FUNCTION "Gest Automatico Linea" : VOID
TITLE =Gestione Ciclo Automatico
AUTHOR : MassimoZ
FAMILY : NovaSrl
VERSION : 0.1

BEGIN
NETWORK
TITLE ======== Ciclo Automatico Zona Acc. 1 =======

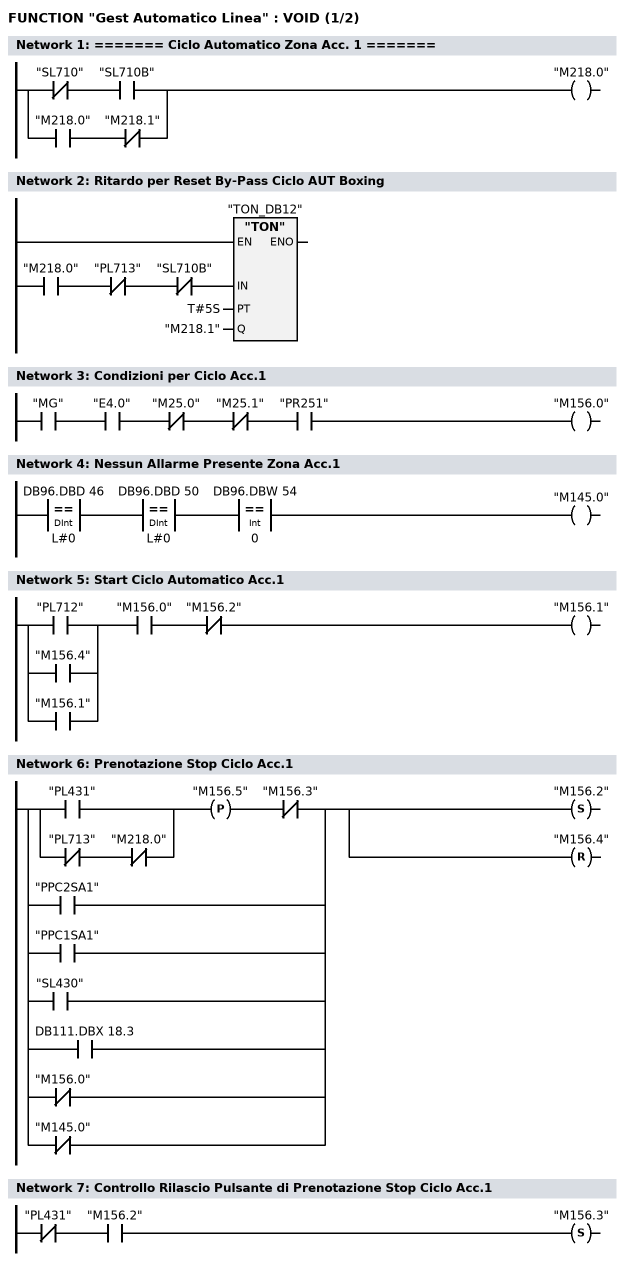
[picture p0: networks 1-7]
      UN    "SL710";
      U     "SL710B";
      O     ;
      U     "M218.0";
      UN    "M218.1";
      =     "M218.0";
NETWORK
TITLE =Ritardo per Reset By-Pass Ciclo AUT Boxing

      U     "M218.0";
      UN    "PL713";
      UN    "SL710B";
      =     L      0.0;
      BLD   103;
      CALL "TON" , "TON_DB12" (
           IN                       := L      0.0,
           PT                       := T#5S,
           Q                        := "M218.1");

      NOP   0;
NETWORK
TITLE =Condizioni per Ciclo Acc.1

      U     "MG";
      U     "E4.0";
      UN    "M25.0";
      UN    "M25.1";
      U     "PR251";
      =     "M156.0";
NETWORK
TITLE =Nessun Allarme Presente Zona Acc.1

      U(    ;
      L     DB96.DBD   46;
      L     L#0;
      ==D   ;
      )     ;
      U(    ;
      L     DB96.DBD   50;
      L     L#0;
      ==D   ;
      )     ;
      U(    ;
      L     DB96.DBW   54;
      L     0;
      ==I   ;
      )     ;
      =     "M145.0";
NETWORK
TITLE =Start Ciclo Automatico Acc.1

      U(    ;
      O     "PL712";
      O     "M156.4";
      O     "M156.1";
      )     ;
      U     "M156.0";
      UN    "M156.2";
      =     "M156.1";
NETWORK
TITLE =Prenotazione Stop Ciclo Acc.1

      U(    ;
      O     "PL431";
      O     ;
      UN    "PL713";
      UN    "M218.0";
      )     ;
      FP    "M156.5";
      UN    "M156.3";
      O     "PPC2SA1";
      O     "PPC1SA1";
      O     "SL430";
      O     DB111.DBX   18.3;
      ON    "M156.0";
      ON    "M145.0";
      S     "M156.2";
      R     "M156.4";
NETWORK
TITLE =Controllo Rilascio Pulsante di Prenotazione Stop Ciclo Acc.1

      UN    "PL431";
      U     "M156.2";
      S     "M156.3";
NETWORK
TITLE =Riavviamento Ciclo dopo Prenotazione Stop Ciclo Acc.1

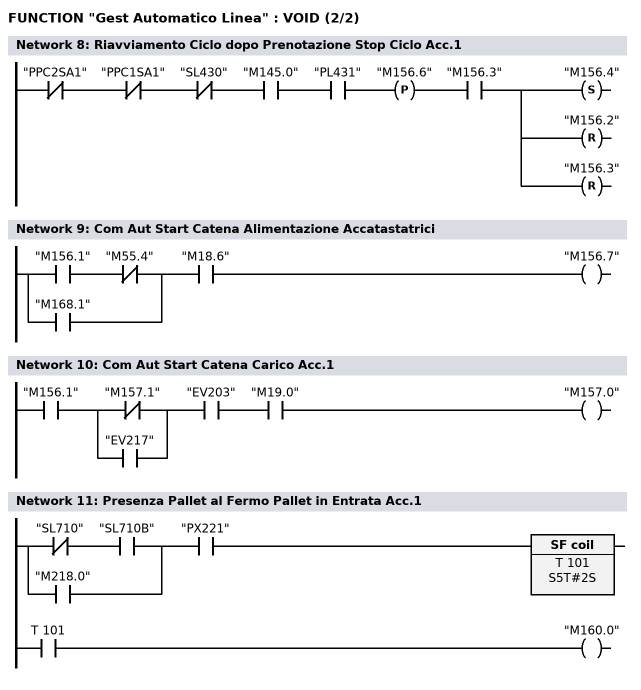
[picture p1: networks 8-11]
      UN    "PPC2SA1";
      UN    "PPC1SA1";
      UN    "SL430";
      U     "M145.0";
      U     "PL431";
      FP    "M156.6";
      U     "M156.3";
      S     "M156.4";
      R     "M156.2";
      R     "M156.3";
NETWORK
TITLE =Com Aut Start Catena Alimentazione Accatastatrici

      U(    ;
      U     "M156.1";
      UN    "M55.4";
      O     "M168.1";
      )     ;
      U     "M18.6";
      =     "M156.7";
NETWORK
TITLE =Com Aut Start Catena Carico Acc.1

      U     "M156.1";
      U(    ;
      ON    "M157.1";
      O     "EV217";
      )     ;
      U     "EV203";
      U     "M19.0";
      =     "M157.0";
NETWORK
TITLE =Presenza Pallet al Fermo Pallet in Entrata Acc.1

      U(    ;
      UN    "SL710";
      U     "SL710B";
      O     "M218.0";
      )     ;
      U     "PX221";
      L     S5T#2S;
      SA    T    101;
      NOP   0;
      NOP   0;
      NOP   0;
      U     T    101;
      =     "M160.0";
NETWORK
TITLE =Presenza Pallet in Posizione di Arrivo Acc.1

      U(    ;
      U(    ;
      UN    "SL710";
      U     "SL710B";
      O     "M218.0";
      )     ;
      U     "PX222";
      L     S5T#2S;
      SE    T     16;
      NOP   0;
      NOP   0;
      NOP   0;
      U     T     16;
      )     ;
      L     S5T#4S;
      SA    T     23;
      NOP   0;
      NOP   0;
      NOP   0;
      U     T     23;
      =     "M157.1";
NETWORK
TITLE =Presenza Pallet in Posizione Carico 1 Acc.1

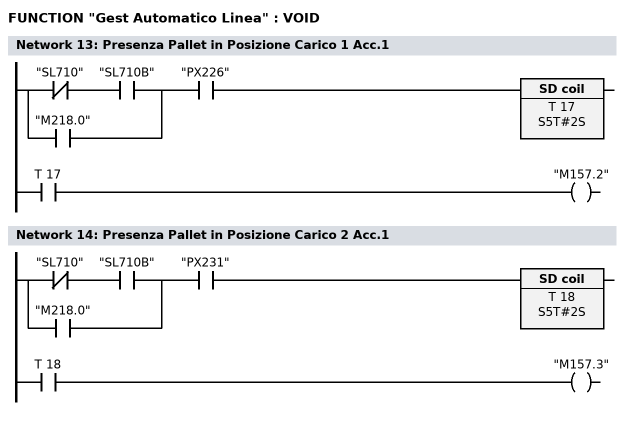
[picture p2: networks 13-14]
      U(    ;
      UN    "SL710";
      U     "SL710B";
      O     "M218.0";
      )     ;
      U     "PX226";
      L     S5T#2S;
      SE    T     17;
      NOP   0;
      NOP   0;
      NOP   0;
      U     T     17;
      =     "M157.2";
NETWORK
TITLE =Presenza Pallet in Posizione Carico 2 Acc.1

      U(    ;
      UN    "SL710";
      U     "SL710B";
      O     "M218.0";
      )     ;
      U     "PX231";
      L     S5T#2S;
      SE    T     18;
      NOP   0;
      NOP   0;
      NOP   0;
      U     T     18;
      =     "M157.3";
NETWORK
TITLE =Presenza Pallet in Posizione Scarico 2 Acc.1

      U(    ;
      U(    ;
      UN    "SL710";
      U     "SL710B";
      O     "M218.0";
      )     ;
      U     "PX233";
      L     S5T#500MS;
      SE    T     21;
      NOP   0;
      NOP   0;
      NOP   0;
      U     T     21;
      )     ;
      L     S5T#2S;
      SA    T     22;
      NOP   0;
      NOP   0;
      NOP   0;
      U     T     22;
      =     "M157.4";
NETWORK
TITLE =Com Aut Salita Fermo Pallet in Uscita per alimentazione Acc.2

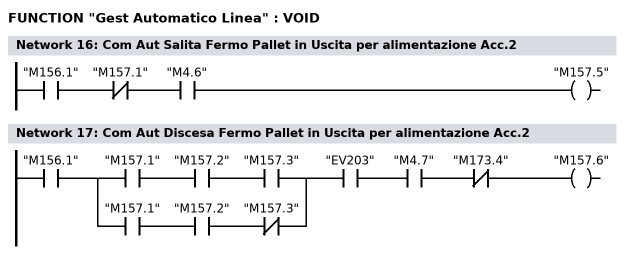
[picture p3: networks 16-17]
      U     "M156.1";
      UN    "M157.1";
      U     "M4.6";
      =     "M157.5";
NETWORK
TITLE =Com Aut Discesa Fermo Pallet in Uscita per alimentazione Acc.2

      U     "M156.1";
      U(    ;
      U     "M157.1";
      U     "M157.2";
      U     "M157.3";
      O     ;
      U     "M157.1";
      U     "M157.2";
      UN    "M157.3";
      )     ;
      U     "EV203";
      U     "M4.7";
      UN    "M173.4";
      =     "M157.6";
NETWORK
TITLE =Aut Pallet in traslazione verso Acc.2

      U     "M157.6";
      S     "M173.4";
      U(    ;
      U     "PX191";
      L     S5T#1S500MS;
      SA    T    104;
      NOP   0;
      NOP   0;
      NOP   0;
      U     T    104;
      )     ;
      FN    "M173.5";
      R     "M173.4";
      NOP   0;
NETWORK
TITLE =Com Aut Avanti Fermo Pallet in Arrivo Acc.1

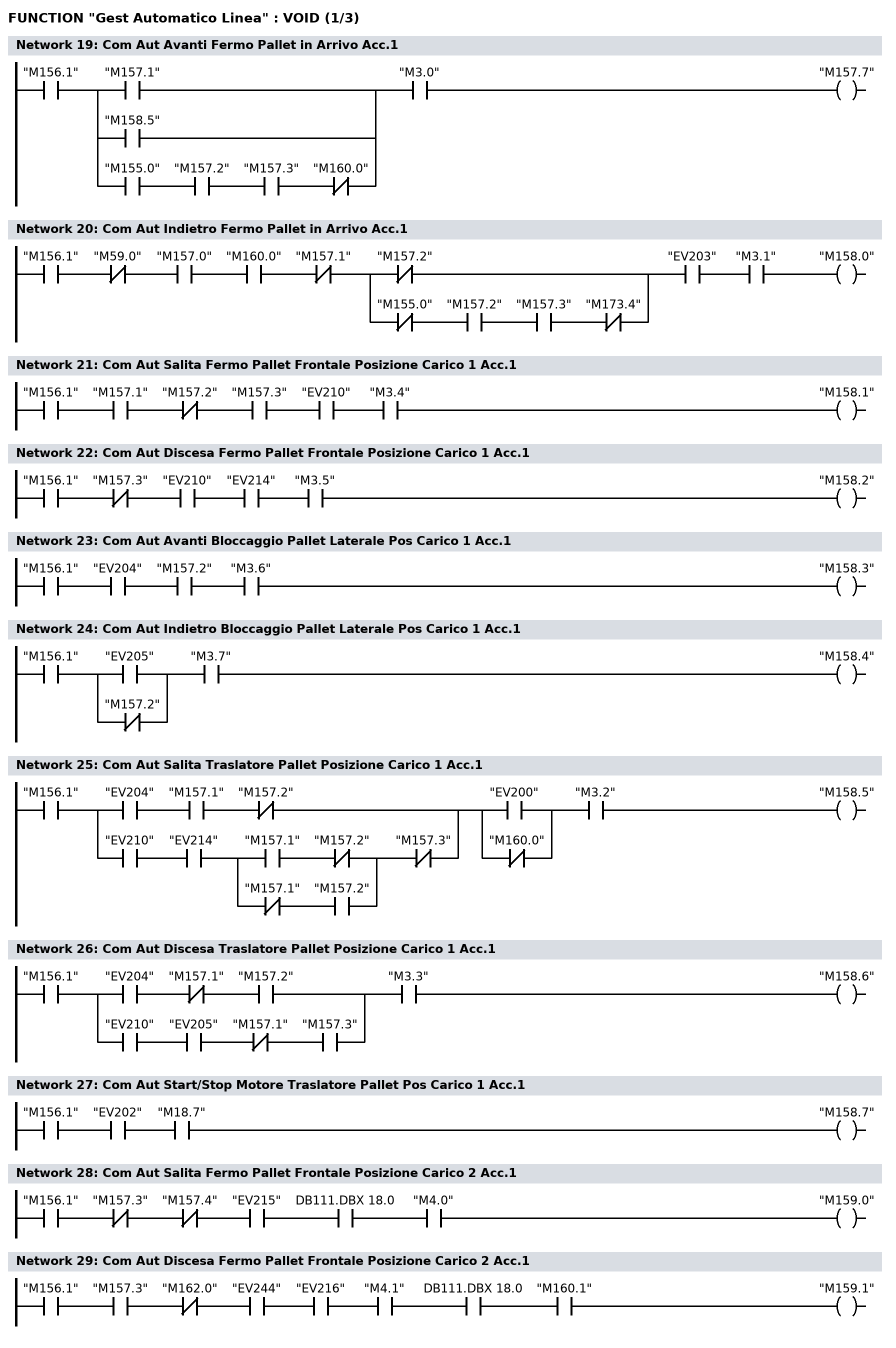
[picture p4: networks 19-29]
      U     "M156.1";
      U(    ;
      O     "M157.1";
      O     "M158.5";
      O     ;
      U     "M155.0";
      U     "M157.2";
      U     "M157.3";
      UN    "M160.0";
      )     ;
      U     "M3.0";
      =     "M157.7";
NETWORK
TITLE =Com Aut Indietro Fermo Pallet in Arrivo Acc.1

      U     "M156.1";
      UN    "M59.0";
      U     "M157.0";
      U     "M160.0";
      UN    "M157.1";
      U(    ;
      ON    "M157.2";
      O     ;
      UN    "M155.0";
      U     "M157.2";
      U     "M157.3";
      UN    "M173.4";
      )     ;
      U     "EV203";
      U     "M3.1";
      =     "M158.0";
NETWORK
TITLE =Com Aut Salita Fermo Pallet Frontale Posizione Carico 1 Acc.1

      U     "M156.1";
      U     "M157.1";
      UN    "M157.2";
      U     "M157.3";
      U     "EV210";
      U     "M3.4";
      =     "M158.1";
NETWORK
TITLE =Com Aut Discesa Fermo Pallet Frontale Posizione Carico 1 Acc.1

      U     "M156.1";
      UN    "M157.3";
      U     "EV210";
      U     "EV214";
      U     "M3.5";
      =     "M158.2";
NETWORK
TITLE =Com Aut Avanti Bloccaggio Pallet Laterale Pos Carico 1 Acc.1

      U     "M156.1";
      U     "EV204";
      U     "M157.2";
      U     "M3.6";
      =     "M158.3";
NETWORK
TITLE =Com Aut Indietro Bloccaggio Pallet Laterale Pos Carico 1 Acc.1

      U     "M156.1";
      U(    ;
      O     "EV205";
      ON    "M157.2";
      )     ;
      U     "M3.7";
      =     "M158.4";
NETWORK
TITLE =Com Aut Salita Traslatore Pallet Posizione Carico 1 Acc.1

      U     "M156.1";
      U(    ;
      U     "EV204";
      U     "M157.1";
      UN    "M157.2";
      O     ;
      U     "EV210";
      U     "EV214";
      U(    ;
      U     "M157.1";
      UN    "M157.2";
      O     ;
      UN    "M157.1";
      U     "M157.2";
      )     ;
      UN    "M157.3";
      )     ;
      U(    ;
      O     "EV200";
      ON    "M160.0";
      )     ;
      U     "M3.2";
      =     "M158.5";
NETWORK
TITLE =Com Aut Discesa Traslatore Pallet Posizione Carico 1 Acc.1

      U     "M156.1";
      U(    ;
      U     "EV204";
      UN    "M157.1";
      U     "M157.2";
      O     ;
      U     "EV210";
      U     "EV205";
      UN    "M157.1";
      U     "M157.3";
      )     ;
      U     "M3.3";
      =     "M158.6";
NETWORK
TITLE =Com Aut Start/Stop Motore Traslatore Pallet Pos Carico 1 Acc.1

      U     "M156.1";
      U     "EV202";
      U     "M18.7";
      =     "M158.7";
NETWORK
TITLE =Com Aut Salita Fermo Pallet Frontale Posizione Carico 2 Acc.1

      U     "M156.1";
      UN    "M157.3";
      UN    "M157.4";
      U     "EV215";
      U     DB111.DBX   18.0;
      U     "M4.0";
      =     "M159.0";
NETWORK
TITLE =Com Aut Discesa Fermo Pallet Frontale Posizione Carico 2 Acc.1

      U     "M156.1";
      U     "M157.3";
      UN    "M162.0";
      U     "EV244";
      U     "EV216";
      U     "M4.1";
      U     DB111.DBX   18.0;
      U     "M160.1";
      =     "M159.1";
NETWORK
TITLE =Com Aut Avanti Bloccaggio Pallet Laterale Pos Carico 2 Acc.1

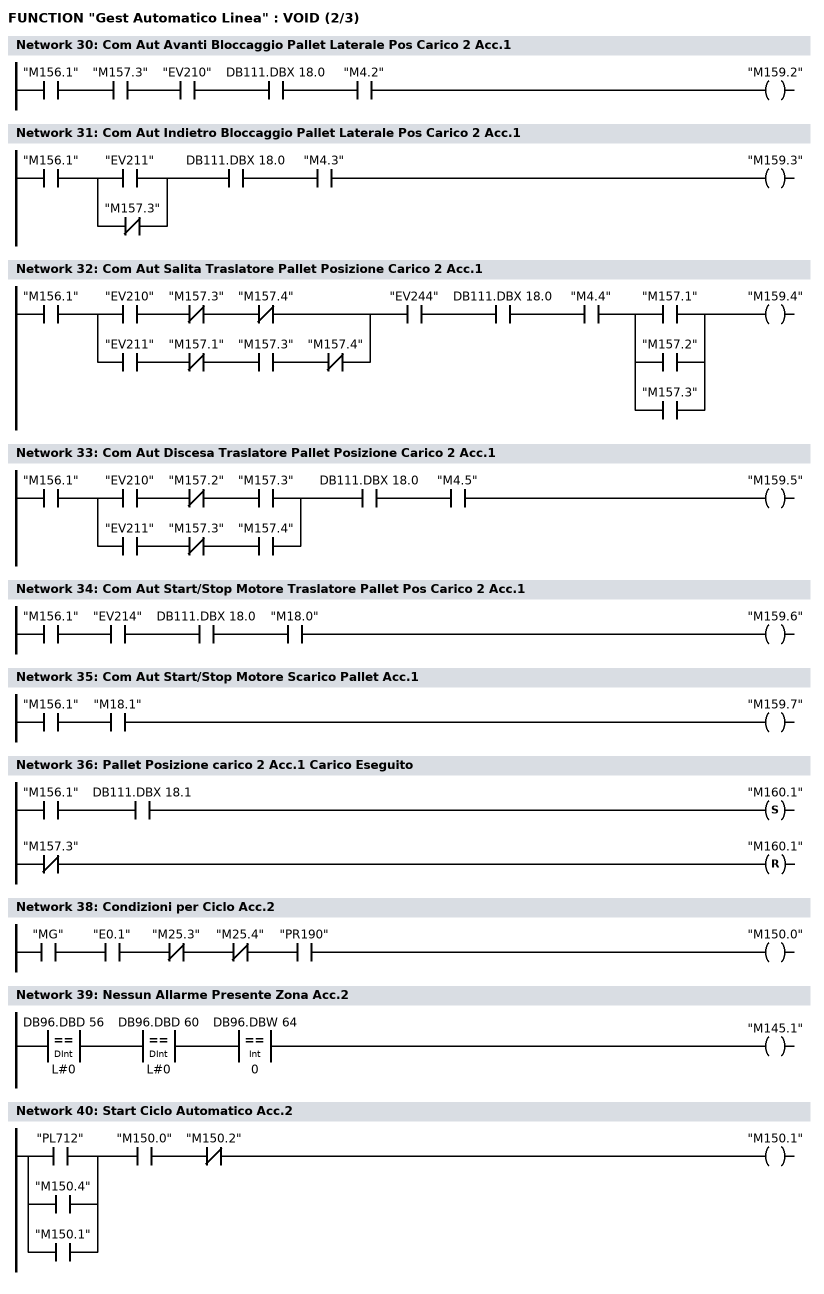
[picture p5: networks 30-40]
      U     "M156.1";
      U     "M157.3";
      U     "EV210";
      U     DB111.DBX   18.0;
      U     "M4.2";
      =     "M159.2";
NETWORK
TITLE =Com Aut Indietro Bloccaggio Pallet Laterale Pos Carico 2 Acc.1

      U     "M156.1";
      U(    ;
      O     "EV211";
      ON    "M157.3";
      )     ;
      U     DB111.DBX   18.0;
      U     "M4.3";
      =     "M159.3";
NETWORK
TITLE =Com Aut Salita Traslatore Pallet Posizione Carico 2 Acc.1

      U     "M156.1";
      U(    ;
      U     "EV210";
      UN    "M157.3";
      UN    "M157.4";
      O     ;
      U     "EV211";
      UN    "M157.1";
      U     "M157.3";
      UN    "M157.4";
      )     ;
      U     "EV244";
      U     DB111.DBX   18.0;
      U     "M4.4";
      U(    ;
      O     "M157.1";
      O     "M157.2";
      O     "M157.3";
      )     ;
      =     "M159.4";
NETWORK
TITLE =Com Aut Discesa Traslatore Pallet Posizione Carico 2 Acc.1

      U     "M156.1";
      U(    ;
      U     "EV210";
      UN    "M157.2";
      U     "M157.3";
      O     ;
      U     "EV211";
      UN    "M157.3";
      U     "M157.4";
      )     ;
      U     DB111.DBX   18.0;
      U     "M4.5";
      =     "M159.5";
NETWORK
TITLE =Com Aut Start/Stop Motore Traslatore Pallet Pos Carico 2 Acc.1

      U     "M156.1";
      U     "EV214";
      U     DB111.DBX   18.0;
      U     "M18.0";
      =     "M159.6";
NETWORK
TITLE =Com Aut Start/Stop Motore Scarico Pallet Acc.1

      U     "M156.1";
      U     "M18.1";
      =     "M159.7";
NETWORK
TITLE =Pallet Posizione carico 2 Acc.1 Carico Eseguito

      U     "M156.1";
      U     DB111.DBX   18.1;
      S     "M160.1";
      UN    "M157.3";
      R     "M160.1";
      NOP   0;
NETWORK
TITLE ======== Ciclo Automatico Zona Acc. 2 =======



NETWORK
TITLE =Condizioni per Ciclo Acc.2

      U     "MG";
      U     "E0.1";
      UN    "M25.3";
      UN    "M25.4";
      U     "PR190";
      =     "M150.0";
NETWORK
TITLE =Nessun Allarme Presente Zona Acc.2

      U(    ;
      L     DB96.DBD   56;
      L     L#0;
      ==D   ;
      )     ;
      U(    ;
      L     DB96.DBD   60;
      L     L#0;
      ==D   ;
      )     ;
      U(    ;
      L     DB96.DBW   64;
      L     0;
      ==I   ;
      )     ;
      =     "M145.1";
NETWORK
TITLE =Start Ciclo Automatico Acc.2

      U(    ;
      O     "PL712";
      O     "M150.4";
      O     "M150.1";
      )     ;
      U     "M150.0";
      UN    "M150.2";
      =     "M150.1";
NETWORK
TITLE =Prenotazione Stop Ciclo Acc.2

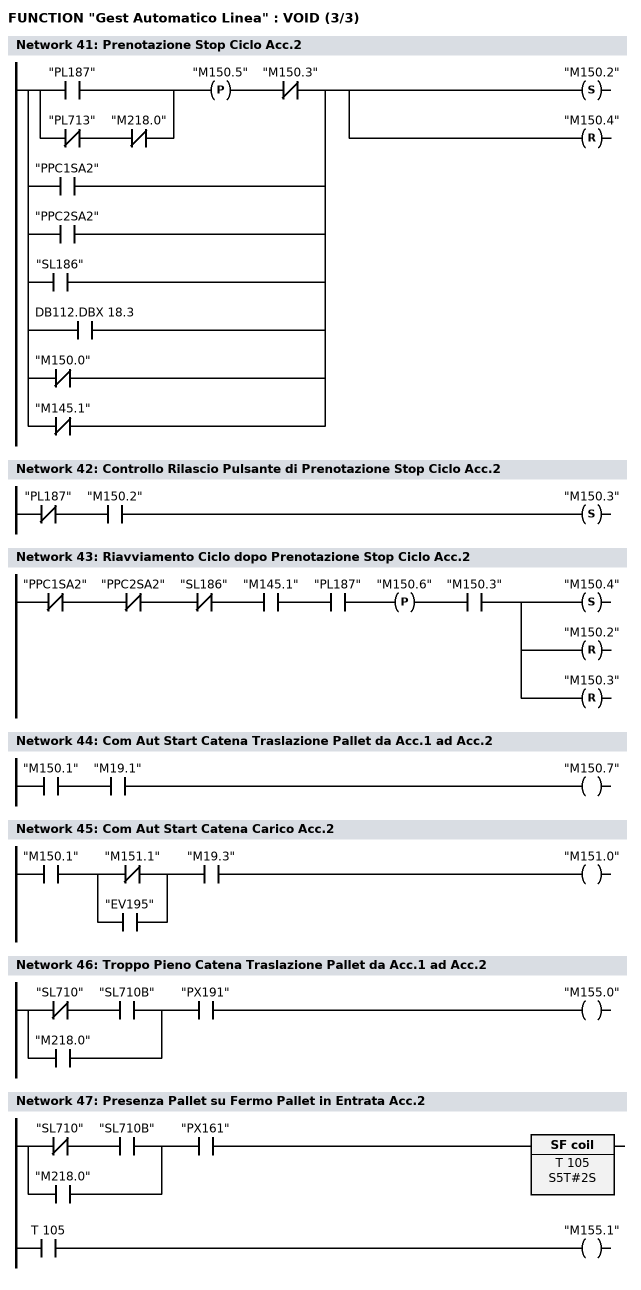
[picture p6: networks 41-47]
      U(    ;
      O     "PL187";
      O     ;
      UN    "PL713";
      UN    "M218.0";
      )     ;
      FP    "M150.5";
      UN    "M150.3";
      O     "PPC1SA2";
      O     "PPC2SA2";
      O     "SL186";
      O     DB112.DBX   18.3;
      ON    "M150.0";
      ON    "M145.1";
      S     "M150.2";
      R     "M150.4";
NETWORK
TITLE =Controllo Rilascio Pulsante di Prenotazione Stop Ciclo Acc.2

      UN    "PL187";
      U     "M150.2";
      S     "M150.3";
NETWORK
TITLE =Riavviamento Ciclo dopo Prenotazione Stop Ciclo Acc.2

      UN    "PPC1SA2";
      UN    "PPC2SA2";
      UN    "SL186";
      U     "M145.1";
      U     "PL187";
      FP    "M150.6";
      U     "M150.3";
      S     "M150.4";
      R     "M150.2";
      R     "M150.3";
NETWORK
TITLE =Com Aut Start Catena Traslazione Pallet da Acc.1 ad Acc.2

      U     "M150.1";
      U     "M19.1";
      =     "M150.7";
NETWORK
TITLE =Com Aut Start Catena Carico Acc.2

      U     "M150.1";
      U(    ;
      ON    "M151.1";
      O     "EV195";
      )     ;
      U     "M19.3";
      =     "M151.0";
NETWORK
TITLE =Troppo Pieno Catena Traslazione Pallet da Acc.1 ad Acc.2

      U(    ;
      UN    "SL710";
      U     "SL710B";
      O     "M218.0";
      )     ;
      U     "PX191";
      =     "M155.0";
NETWORK
TITLE =Presenza Pallet su Fermo Pallet in Entrata Acc.2

      U(    ;
      UN    "SL710";
      U     "SL710B";
      O     "M218.0";
      )     ;
      U     "PX161";
      L     S5T#2S;
      SA    T    105;
      NOP   0;
      NOP   0;
      NOP   0;
      U     T    105;
      =     "M155.1";
NETWORK
TITLE =Presenza Pallet in Posizione di Arrivo Acc.2

      U(    ;
      U(    ;
      UN    "SL710";
      U     "SL710B";
      O     "M218.0";
      )     ;
      U     "PX162";
      L     S5T#2S;
      SE    T      0;
      NOP   0;
      NOP   0;
      NOP   0;
      U     T      0;
      )     ;
      L     S5T#3S;
      SA    T    102;
      NOP   0;
      NOP   0;
      NOP   0;
      U     T    102;
      =     "M151.1";
NETWORK
TITLE =Presenza Pallet in Posizione Carico 1 Acc.2

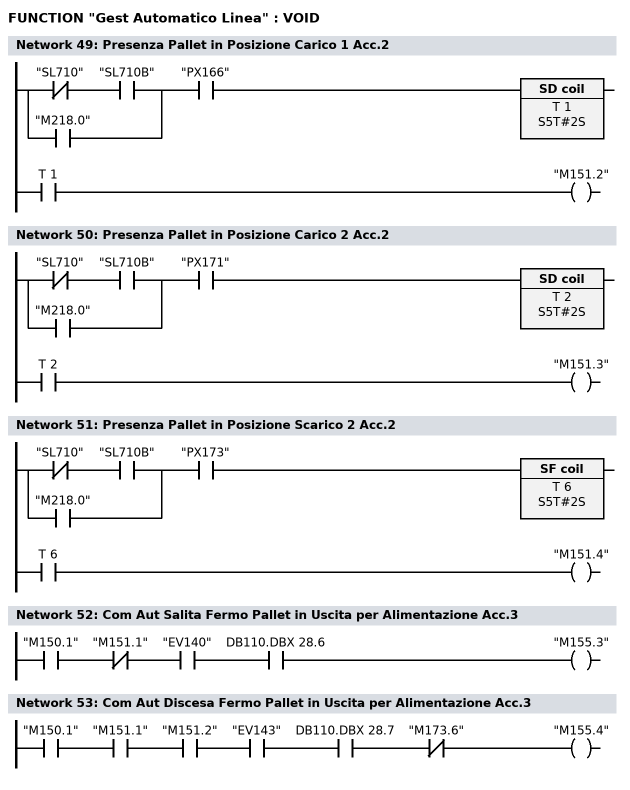
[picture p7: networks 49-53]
      U(    ;
      UN    "SL710";
      U     "SL710B";
      O     "M218.0";
      )     ;
      U     "PX166";
      L     S5T#2S;
      SE    T      1;
      NOP   0;
      NOP   0;
      NOP   0;
      U     T      1;
      =     "M151.2";
NETWORK
TITLE =Presenza Pallet in Posizione Carico 2 Acc.2

      U(    ;
      UN    "SL710";
      U     "SL710B";
      O     "M218.0";
      )     ;
      U     "PX171";
      L     S5T#2S;
      SE    T      2;
      NOP   0;
      NOP   0;
      NOP   0;
      U     T      2;
      =     "M151.3";
NETWORK
TITLE =Presenza Pallet in Posizione Scarico 2 Acc.2

      U(    ;
      UN    "SL710";
      U     "SL710B";
      O     "M218.0";
      )     ;
      U     "PX173";
      L     S5T#2S;
      SA    T      6;
      NOP   0;
      NOP   0;
      NOP   0;
      U     T      6;
      =     "M151.4";
NETWORK
TITLE =Com Aut Salita Fermo Pallet in Uscita per Alimentazione Acc.3

      U     "M150.1";
      UN    "M151.1";
      U     "EV140";
      U     DB110.DBX   28.6;
      =     "M155.3";
NETWORK
TITLE =Com Aut Discesa Fermo Pallet in Uscita per Alimentazione Acc.3

      U     "M150.1";
      U     "M151.1";
      U     "M151.2";
      U     "EV143";
      U     DB110.DBX   28.7;
      UN    "M173.6";
      =     "M155.4";
NETWORK
TITLE =Aut Pallet in traslazione verso Acc.3

      U     "M155.4";
      S     "M173.6";
      U(    ;
      U     "PX811";
      L     S5T#1S500MS;
      SA    T      5;
      NOP   0;
      NOP   0;
      NOP   0;
      U     T      5;
      )     ;
      FN    "M173.7";
      R     "M173.6";
      NOP   0;
NETWORK
TITLE =Com Aut Avanti Fermo Pallet in Arrivo Acc.2

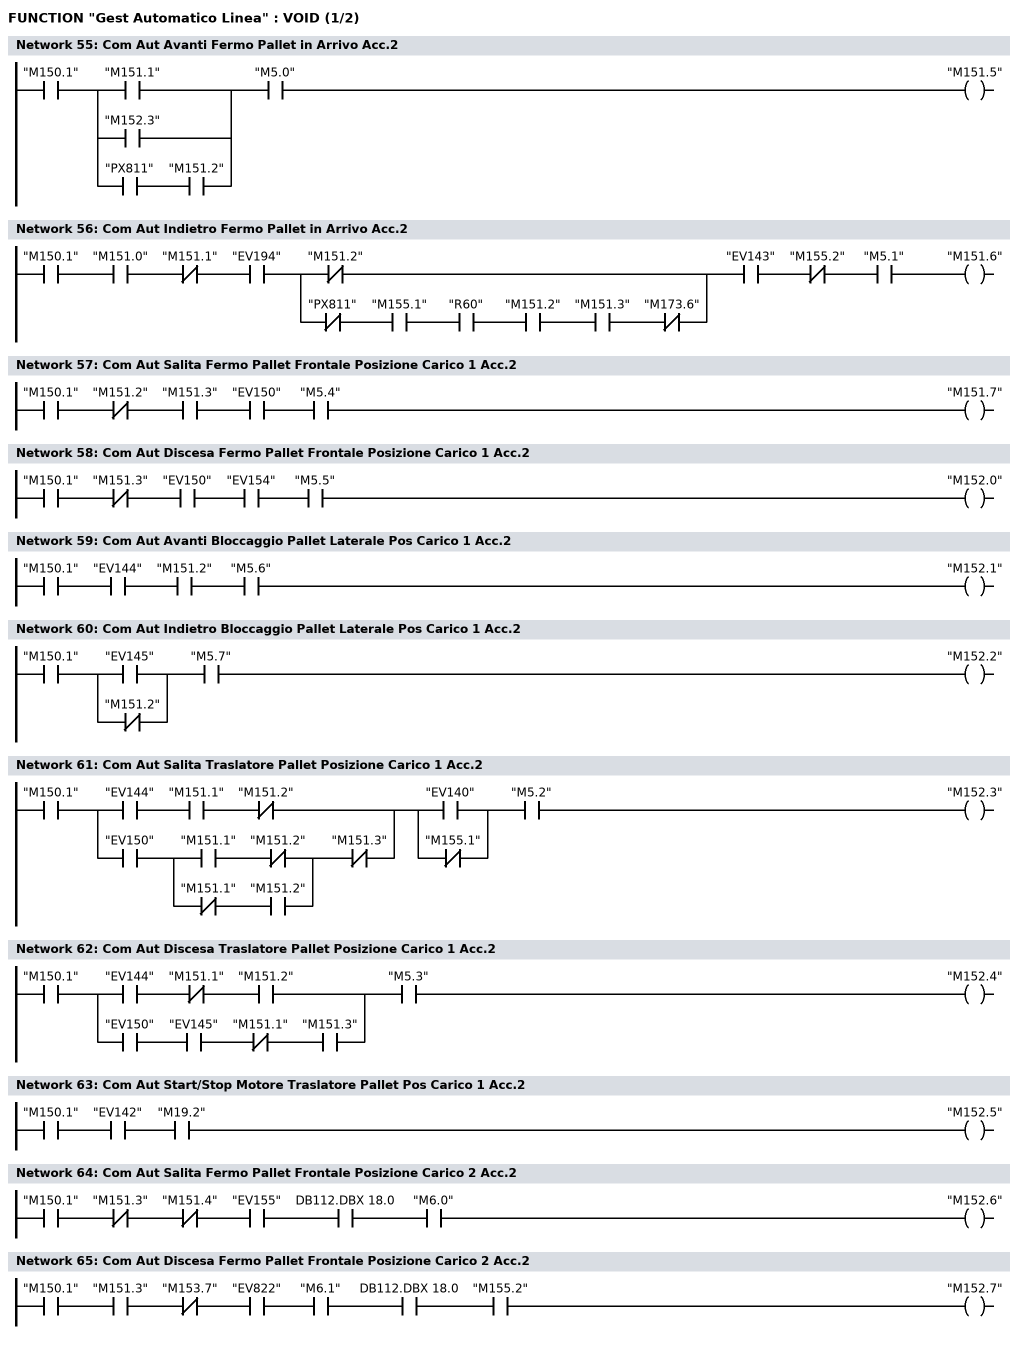
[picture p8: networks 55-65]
      U     "M150.1";
      U(    ;
      O     "M151.1";
      O     "M152.3";
      O     ;
      U     "PX811";
      U     "M151.2";
      )     ;
      U     "M5.0";
      =     "M151.5";
NETWORK
TITLE =Com Aut Indietro Fermo Pallet in Arrivo Acc.2

      U     "M150.1";
      U     "M151.0";
      UN    "M151.1";
      U     "EV194";
      U(    ;
      ON    "M151.2";
      O     ;
      UN    "PX811";
      U     "M155.1";
      U     "R60";
      U     "M151.2";
      U     "M151.3";
      UN    "M173.6";
      )     ;
      U     "EV143";
      UN    "M155.2";
      U     "M5.1";
      =     "M151.6";
NETWORK
TITLE =Com Aut Salita Fermo Pallet Frontale Posizione Carico 1 Acc.2

      U     "M150.1";
      UN    "M151.2";
      U     "M151.3";
      U     "EV150";
      U     "M5.4";
      =     "M151.7";
NETWORK
TITLE =Com Aut Discesa Fermo Pallet Frontale Posizione Carico 1 Acc.2

      U     "M150.1";
      UN    "M151.3";
      U     "EV150";
      U     "EV154";
      U     "M5.5";
      =     "M152.0";
NETWORK
TITLE =Com Aut Avanti Bloccaggio Pallet Laterale Pos Carico 1 Acc.2

      U     "M150.1";
      U     "EV144";
      U     "M151.2";
      U     "M5.6";
      =     "M152.1";
NETWORK
TITLE =Com Aut Indietro Bloccaggio Pallet Laterale Pos Carico 1 Acc.2

      U     "M150.1";
      U(    ;
      O     "EV145";
      ON    "M151.2";
      )     ;
      U     "M5.7";
      =     "M152.2";
NETWORK
TITLE =Com Aut Salita Traslatore Pallet Posizione Carico 1 Acc.2

      U     "M150.1";
      U(    ;
      U     "EV144";
      U     "M151.1";
      UN    "M151.2";
      O     ;
      U     "EV150";
      U(    ;
      U     "M151.1";
      UN    "M151.2";
      O     ;
      UN    "M151.1";
      U     "M151.2";
      )     ;
      UN    "M151.3";
      )     ;
      U(    ;
      O     "EV140";
      ON    "M155.1";
      )     ;
      U     "M5.2";
      =     "M152.3";
NETWORK
TITLE =Com Aut Discesa Traslatore Pallet Posizione Carico 1 Acc.2

      U     "M150.1";
      U(    ;
      U     "EV144";
      UN    "M151.1";
      U     "M151.2";
      O     ;
      U     "EV150";
      U     "EV145";
      UN    "M151.1";
      U     "M151.3";
      )     ;
      U     "M5.3";
      =     "M152.4";
NETWORK
TITLE =Com Aut Start/Stop Motore Traslatore Pallet Pos Carico 1 Acc.2

      U     "M150.1";
      U     "EV142";
      U     "M19.2";
      =     "M152.5";
NETWORK
TITLE =Com Aut Salita Fermo Pallet Frontale Posizione Carico 2 Acc.2

      U     "M150.1";
      UN    "M151.3";
      UN    "M151.4";
      U     "EV155";
      U     DB112.DBX   18.0;
      U     "M6.0";
      =     "M152.6";
NETWORK
TITLE =Com Aut Discesa Fermo Pallet Frontale Posizione Carico 2 Acc.2

      U     "M150.1";
      U     "M151.3";
      UN    "M153.7";
      U     "EV822";
      U     "M6.1";
      U     DB112.DBX   18.0;
      U     "M155.2";
      =     "M152.7";
NETWORK
TITLE =Com Aut Avanti Bloccaggio Pallet Laterale Pos Carico 2 Acc.2

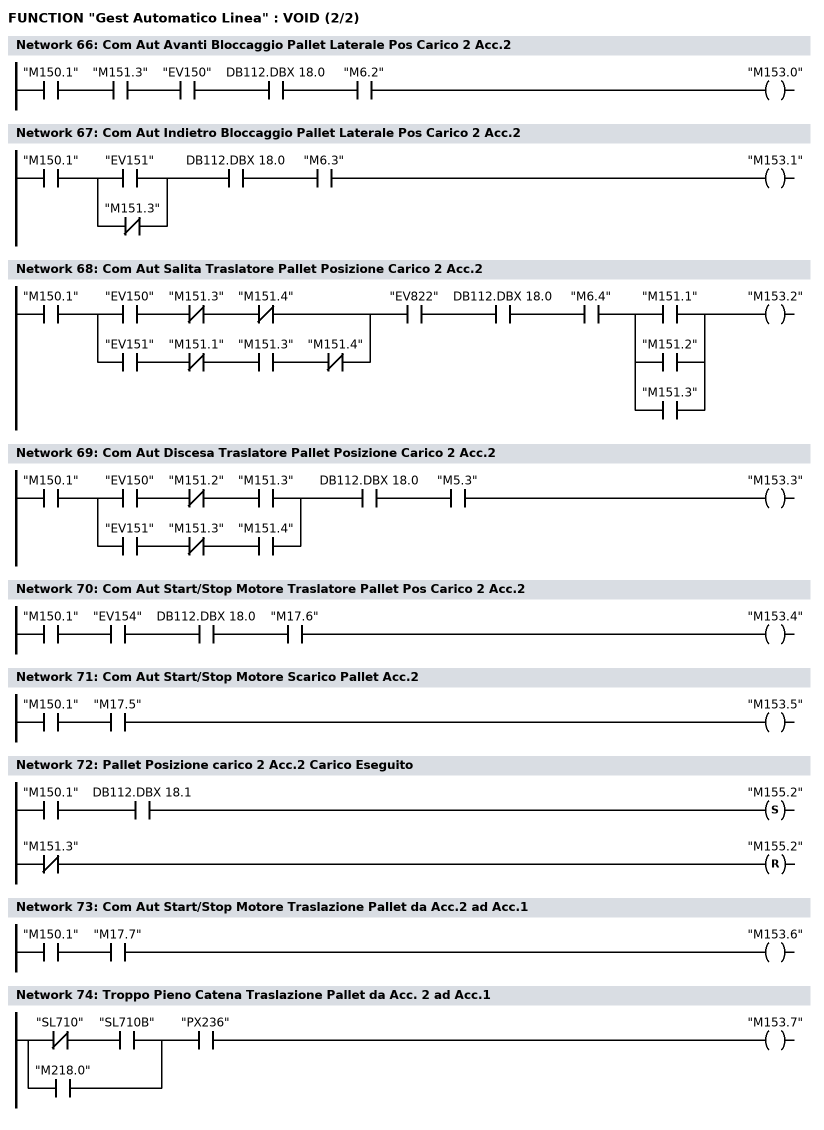
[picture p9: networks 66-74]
      U     "M150.1";
      U     "M151.3";
      U     "EV150";
      U     DB112.DBX   18.0;
      U     "M6.2";
      =     "M153.0";
NETWORK
TITLE =Com Aut Indietro Bloccaggio Pallet Laterale Pos Carico 2 Acc.2

      U     "M150.1";
      U(    ;
      O     "EV151";
      ON    "M151.3";
      )     ;
      U     DB112.DBX   18.0;
      U     "M6.3";
      =     "M153.1";
NETWORK
TITLE =Com Aut Salita Traslatore Pallet Posizione Carico 2 Acc.2

      U     "M150.1";
      U(    ;
      U     "EV150";
      UN    "M151.3";
      UN    "M151.4";
      O     ;
      U     "EV151";
      UN    "M151.1";
      U     "M151.3";
      UN    "M151.4";
      )     ;
      U     "EV822";
      U     DB112.DBX   18.0;
      U     "M6.4";
      U(    ;
      O     "M151.1";
      O     "M151.2";
      O     "M151.3";
      )     ;
      =     "M153.2";
NETWORK
TITLE =Com Aut Discesa Traslatore Pallet Posizione Carico 2 Acc.2

      U     "M150.1";
      U(    ;
      U     "EV150";
      UN    "M151.2";
      U     "M151.3";
      O     ;
      U     "EV151";
      UN    "M151.3";
      U     "M151.4";
      )     ;
      U     DB112.DBX   18.0;
      U     "M5.3";
      =     "M153.3";
NETWORK
TITLE =Com Aut Start/Stop Motore Traslatore Pallet Pos Carico 2 Acc.2

      U     "M150.1";
      U     "EV154";
      U     DB112.DBX   18.0;
      U     "M17.6";
      =     "M153.4";
NETWORK
TITLE =Com Aut Start/Stop Motore Scarico Pallet Acc.2

      U     "M150.1";
      U     "M17.5";
      =     "M153.5";
NETWORK
TITLE =Pallet Posizione carico 2 Acc.2 Carico Eseguito

      U     "M150.1";
      U     DB112.DBX   18.1;
      S     "M155.2";
      UN    "M151.3";
      R     "M155.2";
      NOP   0;
NETWORK
TITLE =Com Aut Start/Stop Motore Traslazione Pallet da Acc.2 ad Acc.1

      U     "M150.1";
      U     "M17.7";
      =     "M153.6";
NETWORK
TITLE =Troppo Pieno Catena Traslazione Pallet da Acc. 2 ad Acc.1

      U(    ;
      UN    "SL710";
      U     "SL710B";
      O     "M218.0";
      )     ;
      U     "PX236";
      =     "M153.7";
NETWORK
TITLE =Presenza Pallet Secondo Fermo Pallet da Acc.2

      U(    ;
      U(    ;
      UN    "SL710";
      U     "SL710B";
      O     "M218.0";
      )     ;
      U     "PX246";
      L     S5T#2S;
      SE    T      9;
      NOP   0;
      NOP   0;
      NOP   0;
      U     T      9;
      )     ;
      L     S5T#4S;
      SA    T     10;
      NOP   0;
      NOP   0;
      NOP   0;
      U     T     10;
      =     "M154.0";
NETWORK
TITLE =Presenza Pallet Terzo Fermo Pallet da Acc.2

      U(    ;
      U(    ;
      UN    "SL710";
      U     "SL710B";
      O     "M218.0";
      )     ;
      U     "PX250";
      L     S5T#2S;
      SE    T     14;
      NOP   0;
      NOP   0;
      NOP   0;
      U     T     14;
      )     ;
      L     S5T#6S;
      SA    T     15;
      NOP   0;
      NOP   0;
      NOP   0;
      U     T     15;
      =     "M154.1";
NETWORK
TITLE =Com Aut Avanti Primo Fermo Pallet da Acc.2

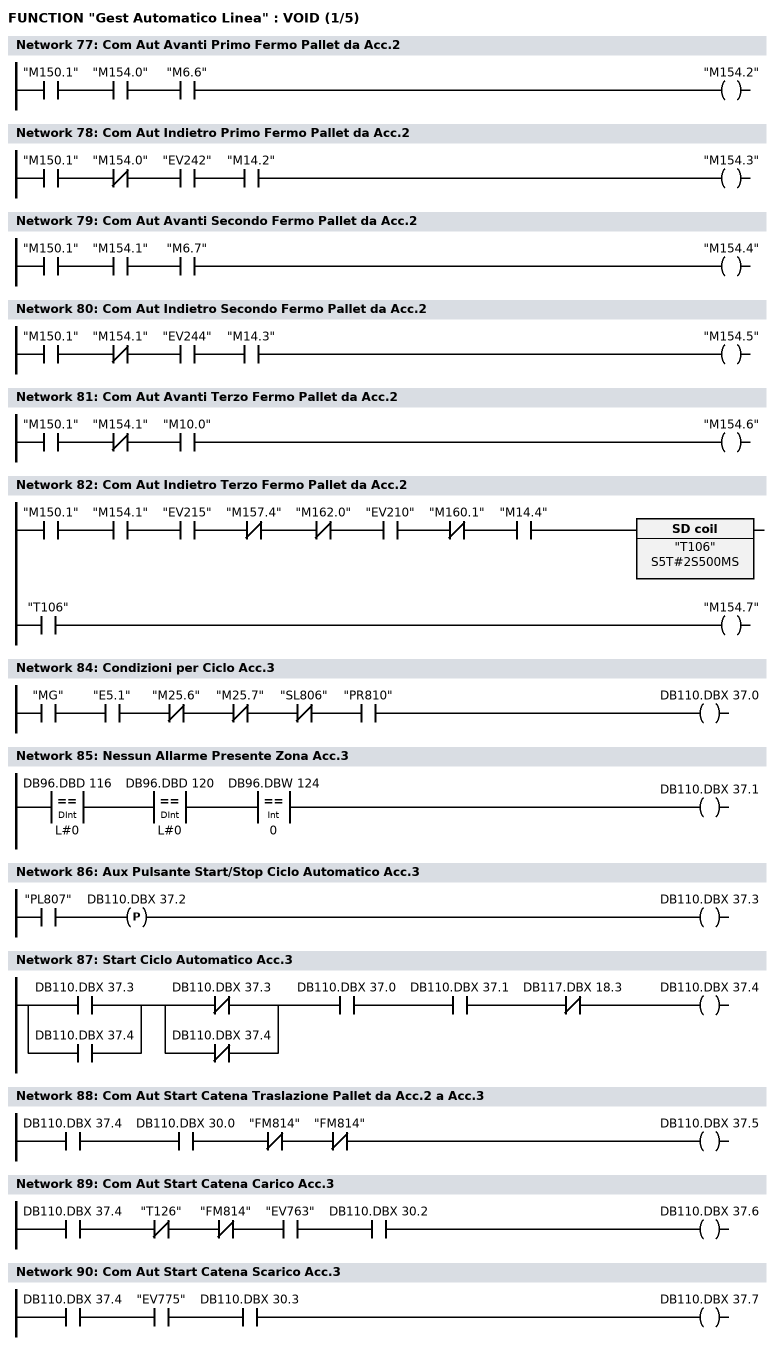
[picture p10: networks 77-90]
      U     "M150.1";
      U     "M154.0";
      U     "M6.6";
      =     "M154.2";
NETWORK
TITLE =Com Aut Indietro Primo Fermo Pallet da Acc.2

      U     "M150.1";
      UN    "M154.0";
      U     "EV242";
      U     "M14.2";
      =     "M154.3";
NETWORK
TITLE =Com Aut Avanti Secondo Fermo Pallet da Acc.2

      U     "M150.1";
      U     "M154.1";
      U     "M6.7";
      =     "M154.4";
NETWORK
TITLE =Com Aut Indietro Secondo Fermo Pallet da Acc.2

      U     "M150.1";
      UN    "M154.1";
      U     "EV244";
      U     "M14.3";
      =     "M154.5";
NETWORK
TITLE =Com Aut Avanti Terzo Fermo Pallet da Acc.2

      U     "M150.1";
      UN    "M154.1";
      U     "M10.0";
      =     "M154.6";
NETWORK
TITLE =Com Aut Indietro Terzo Fermo Pallet da Acc.2

      U     "M150.1";
      U     "M154.1";
      U     "EV215";
      UN    "M157.4";
      UN    "M162.0";
      U     "EV210";
      UN    "M160.1";
      U     "M14.4";
      L     S5T#2S500MS;
      SE    "T106";
      NOP   0;
      NOP   0;
      NOP   0;
      U     "T106";
      =     "M154.7";
NETWORK
TITLE ======== Ciclo Automatico Zona Acc. 3 =======



NETWORK
TITLE =Condizioni per Ciclo Acc.3

      U     "MG";
      U     "E5.1";
      UN    "M25.6";
      UN    "M25.7";
      UN    "SL806";
      U     "PR810";
      =     DB110.DBX   37.0;
NETWORK
TITLE =Nessun Allarme Presente Zona Acc.3

      U(    ;
      L     DB96.DBD  116;
      L     L#0;
      ==D   ;
      )     ;
      U(    ;
      L     DB96.DBD  120;
      L     L#0;
      ==D   ;
      )     ;
      U(    ;
      L     DB96.DBW  124;
      L     0;
      ==I   ;
      )     ;
      =     DB110.DBX   37.1;
NETWORK
TITLE =Aux Pulsante Start/Stop Ciclo Automatico Acc.3

      U     "PL807";
      FP    DB110.DBX   37.2;
      =     DB110.DBX   37.3;
NETWORK
TITLE =Start Ciclo Automatico Acc.3

      U(    ;
      O     DB110.DBX   37.3;
      O     DB110.DBX   37.4;
      )     ;
      U(    ;
      ON    DB110.DBX   37.3;
      ON    DB110.DBX   37.4;
      )     ;
      U     DB110.DBX   37.0;
      U     DB110.DBX   37.1;
      UN    DB117.DBX   18.3;
      =     DB110.DBX   37.4;
NETWORK
TITLE =Com Aut Start Catena Traslazione Pallet da Acc.2 a Acc.3

      U     DB110.DBX   37.4;
      U     DB110.DBX   30.0;
      UN    "FM814";
      UN    "FM814";
      =     DB110.DBX   37.5;
NETWORK
TITLE =Com Aut Start Catena Carico Acc.3

      U     DB110.DBX   37.4;
      UN    "T126";
      UN    "FM814";
      U     "EV763";
      U     DB110.DBX   30.2;
      =     DB110.DBX   37.6;
NETWORK
TITLE =Com Aut Start Catena Scarico Acc.3

      U     DB110.DBX   37.4;
      U     "EV775";
      U     DB110.DBX   30.3;
      =     DB110.DBX   37.7;
NETWORK
TITLE =Com Aut Start Catena Traslazione Pallet da Acc.3 a Acc.2

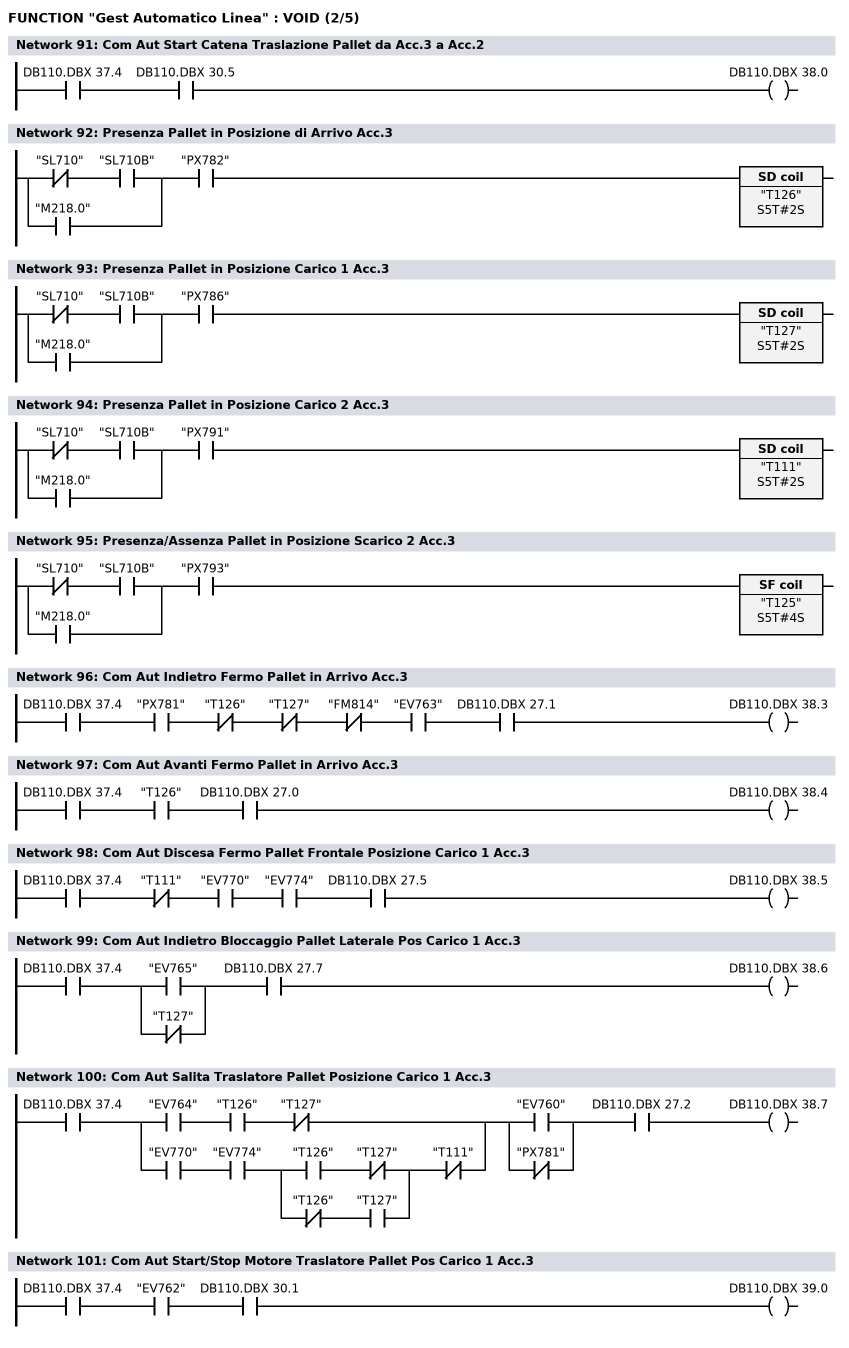
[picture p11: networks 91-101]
      U     DB110.DBX   37.4;
      U     DB110.DBX   30.5;
      =     DB110.DBX   38.0;
NETWORK
TITLE =Presenza Pallet in Posizione di Arrivo Acc.3

      U(    ;
      UN    "SL710";
      U     "SL710B";
      O     "M218.0";
      )     ;
      U     "PX782";
      L     S5T#2S;
      SE    "T126";
NETWORK
TITLE =Presenza Pallet in Posizione Carico 1 Acc.3

      U(    ;
      UN    "SL710";
      U     "SL710B";
      O     "M218.0";
      )     ;
      U     "PX786";
      L     S5T#2S;
      SE    "T127";
NETWORK
TITLE =Presenza Pallet in Posizione Carico 2 Acc.3

      U(    ;
      UN    "SL710";
      U     "SL710B";
      O     "M218.0";
      )     ;
      U     "PX791";
      L     S5T#2S;
      SE    "T111";
NETWORK
TITLE =Presenza/Assenza Pallet in Posizione Scarico 2 Acc.3

      U(    ;
      UN    "SL710";
      U     "SL710B";
      O     "M218.0";
      )     ;
      U     "PX793";
      L     S5T#4S;
      SA    "T125";
NETWORK
TITLE =Com Aut Indietro Fermo Pallet in Arrivo Acc.3

      U     DB110.DBX   37.4;
      U     "PX781";
      UN    "T126";
      UN    "T127";
      UN    "FM814";
      U     "EV763";
      U     DB110.DBX   27.1;
      =     DB110.DBX   38.3;
NETWORK
TITLE =Com Aut Avanti Fermo Pallet in Arrivo Acc.3

      U     DB110.DBX   37.4;
      U     "T126";
      U     DB110.DBX   27.0;
      =     DB110.DBX   38.4;
NETWORK
TITLE =Com Aut Discesa Fermo Pallet Frontale Posizione Carico 1 Acc.3

      U     DB110.DBX   37.4;
      UN    "T111";
      U     "EV770";
      U     "EV774";
      U     DB110.DBX   27.5;
      =     DB110.DBX   38.5;
NETWORK
TITLE =Com Aut Indietro Bloccaggio Pallet Laterale Pos Carico 1 Acc.3

      U     DB110.DBX   37.4;
      U(    ;
      O     "EV765";
      ON    "T127";
      )     ;
      U     DB110.DBX   27.7;
      =     DB110.DBX   38.6;
NETWORK
TITLE =Com Aut Salita Traslatore Pallet Posizione Carico 1 Acc.3

      U     DB110.DBX   37.4;
      U(    ;
      U     "EV764";
      U     "T126";
      UN    "T127";
      O     ;
      U     "EV770";
      U     "EV774";
      U(    ;
      U     "T126";
      UN    "T127";
      O     ;
      UN    "T126";
      U     "T127";
      )     ;
      UN    "T111";
      )     ;
      U(    ;
      O     "EV760";
      ON    "PX781";
      )     ;
      U     DB110.DBX   27.2;
      =     DB110.DBX   38.7;
NETWORK
TITLE =Com Aut Start/Stop Motore Traslatore Pallet Pos Carico 1 Acc.3

      U     DB110.DBX   37.4;
      U     "EV762";
      U     DB110.DBX   30.1;
      =     DB110.DBX   39.0;
NETWORK
TITLE =Com Aut Salita Fermo Pallet Frontale Posizione Carico 2 Acc.3

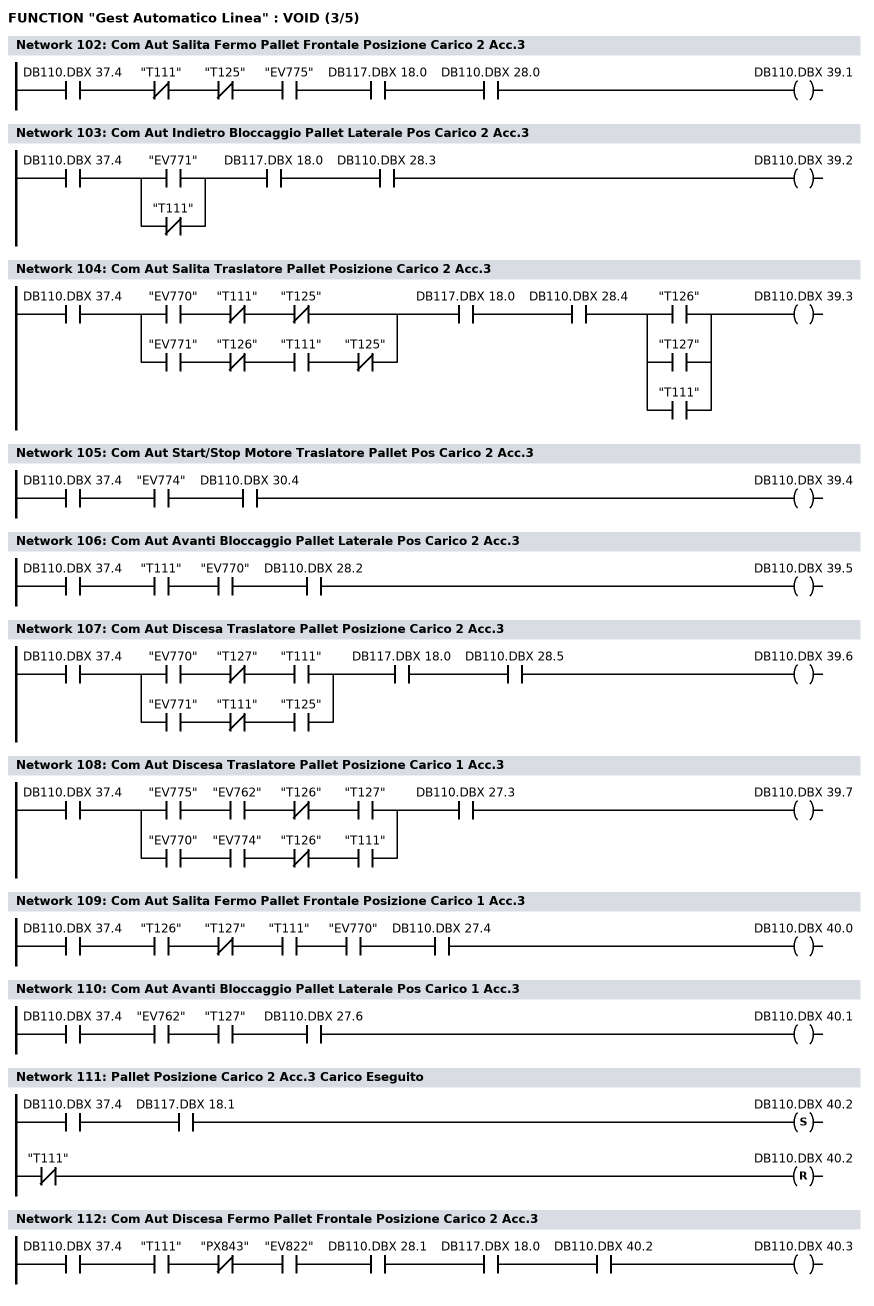
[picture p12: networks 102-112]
      U     DB110.DBX   37.4;
      UN    "T111";
      UN    "T125";
      U     "EV775";
      U     DB117.DBX   18.0;
      U     DB110.DBX   28.0;
      =     DB110.DBX   39.1;
NETWORK
TITLE =Com Aut Indietro Bloccaggio Pallet Laterale Pos Carico 2 Acc.3

      U     DB110.DBX   37.4;
      U(    ;
      O     "EV771";
      ON    "T111";
      )     ;
      U     DB117.DBX   18.0;
      U     DB110.DBX   28.3;
      =     DB110.DBX   39.2;
NETWORK
TITLE =Com Aut Salita Traslatore Pallet Posizione Carico 2 Acc.3

      U     DB110.DBX   37.4;
      U(    ;
      U     "EV770";
      UN    "T111";
      UN    "T125";
      O     ;
      U     "EV771";
      UN    "T126";
      U     "T111";
      UN    "T125";
      )     ;
      U     DB117.DBX   18.0;
      U     DB110.DBX   28.4;
      U(    ;
      O     "T126";
      O     "T127";
      O     "T111";
      )     ;
      =     DB110.DBX   39.3;
NETWORK
TITLE =Com Aut Start/Stop Motore Traslatore Pallet Pos Carico 2 Acc.3

      U     DB110.DBX   37.4;
      U     "EV774";
      U     DB110.DBX   30.4;
      =     DB110.DBX   39.4;
NETWORK
TITLE =Com Aut Avanti Bloccaggio Pallet Laterale Pos Carico 2 Acc.3

      U     DB110.DBX   37.4;
      U     "T111";
      U     "EV770";
      U     DB110.DBX   28.2;
      =     DB110.DBX   39.5;
NETWORK
TITLE =Com Aut Discesa Traslatore Pallet Posizione Carico 2 Acc.3

      U     DB110.DBX   37.4;
      U(    ;
      U     "EV770";
      UN    "T127";
      U     "T111";
      O     ;
      U     "EV771";
      UN    "T111";
      U     "T125";
      )     ;
      U     DB117.DBX   18.0;
      U     DB110.DBX   28.5;
      =     DB110.DBX   39.6;
NETWORK
TITLE =Com Aut Discesa Traslatore Pallet Posizione Carico 1 Acc.3

      U     DB110.DBX   37.4;
      U(    ;
      U     "EV775";
      U     "EV762";
      UN    "T126";
      U     "T127";
      O     ;
      U     "EV770";
      U     "EV774";
      UN    "T126";
      U     "T111";
      )     ;
      U     DB110.DBX   27.3;
      =     DB110.DBX   39.7;
NETWORK
TITLE =Com Aut Salita Fermo Pallet Frontale Posizione Carico 1 Acc.3

      U     DB110.DBX   37.4;
      U     "T126";
      UN    "T127";
      U     "T111";
      U     "EV770";
      U     DB110.DBX   27.4;
      =     DB110.DBX   40.0;
NETWORK
TITLE =Com Aut Avanti Bloccaggio Pallet Laterale Pos Carico 1 Acc.3

      U     DB110.DBX   37.4;
      U     "EV762";
      U     "T127";
      U     DB110.DBX   27.6;
      =     DB110.DBX   40.1;
NETWORK
TITLE =Pallet Posizione Carico 2 Acc.3 Carico Eseguito

      U     DB110.DBX   37.4;
      U     DB117.DBX   18.1;
      S     DB110.DBX   40.2;
      UN    "T111";
      R     DB110.DBX   40.2;
      NOP   0;
NETWORK
TITLE =Com Aut Discesa Fermo Pallet Frontale Posizione Carico 2 Acc.3

      U     DB110.DBX   37.4;
      U     "T111";
      UN    "PX843";
      U     "EV822";
      U     DB110.DBX   28.1;
      U     DB117.DBX   18.0;
      U     DB110.DBX   40.2;
      =     DB110.DBX   40.3;
NETWORK
TITLE =Presenza/Assenza Pallet 2° Fermo Arrivo da Acc.3

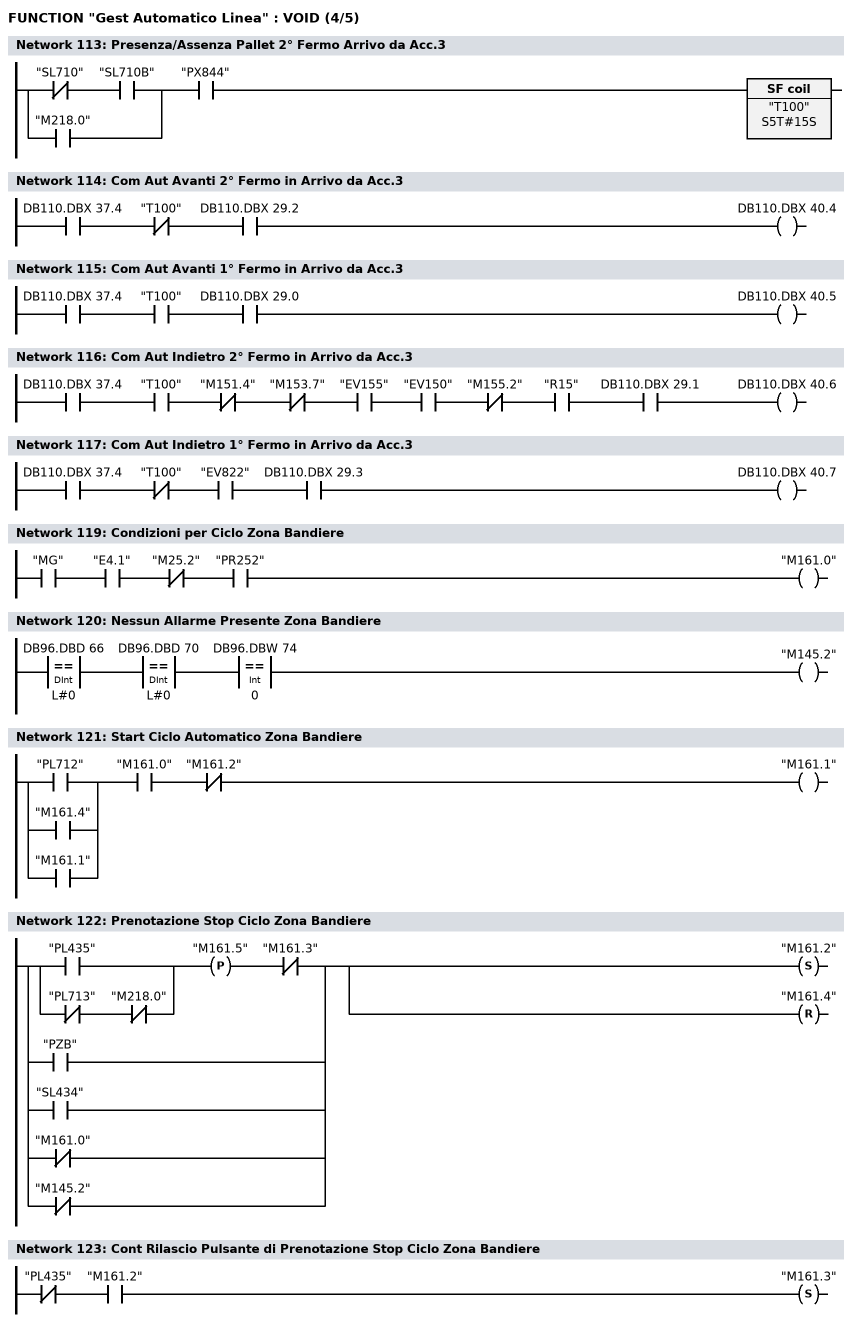
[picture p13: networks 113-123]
      U(    ;
      UN    "SL710";
      U     "SL710B";
      O     "M218.0";
      )     ;
      U     "PX844";
      L     S5T#15S;
      SA    "T100";
NETWORK
TITLE =Com Aut Avanti 2° Fermo in Arrivo da Acc.3

      U     DB110.DBX   37.4;
      UN    "T100";
      U     DB110.DBX   29.2;
      =     DB110.DBX   40.4;
NETWORK
TITLE =Com Aut Avanti 1° Fermo in Arrivo da Acc.3

      U     DB110.DBX   37.4;
      U     "T100";
      U     DB110.DBX   29.0;
      =     DB110.DBX   40.5;
NETWORK
TITLE =Com Aut Indietro 2° Fermo in Arrivo da Acc.3

      U     DB110.DBX   37.4;
      U     "T100";
      UN    "M151.4";
      UN    "M153.7";
      U     "EV155";
      U     "EV150";
      UN    "M155.2";
      U     "R15";
      U     DB110.DBX   29.1;
      =     DB110.DBX   40.6;
NETWORK
TITLE =Com Aut Indietro 1° Fermo in Arrivo da Acc.3

      U     DB110.DBX   37.4;
      UN    "T100";
      U     "EV822";
      U     DB110.DBX   29.3;
      =     DB110.DBX   40.7;
NETWORK
TITLE ======== Ciclo Automatico Zona Bandiere ======



NETWORK
TITLE =Condizioni per Ciclo Zona Bandiere

      U     "MG";
      U     "E4.1";
      UN    "M25.2";
      U     "PR252";
      =     "M161.0";
NETWORK
TITLE =Nessun Allarme Presente Zona Bandiere

      U(    ;
      L     DB96.DBD   66;
      L     L#0;
      ==D   ;
      )     ;
      U(    ;
      L     DB96.DBD   70;
      L     L#0;
      ==D   ;
      )     ;
      U(    ;
      L     DB96.DBW   74;
      L     0;
      ==I   ;
      )     ;
      =     "M145.2";
NETWORK
TITLE =Start Ciclo Automatico Zona Bandiere

      U(    ;
      O     "PL712";
      O     "M161.4";
      O     "M161.1";
      )     ;
      U     "M161.0";
      UN    "M161.2";
      =     "M161.1";
NETWORK
TITLE =Prenotazione Stop Ciclo Zona Bandiere

      U(    ;
      O     "PL435";
      O     ;
      UN    "PL713";
      UN    "M218.0";
      )     ;
      FP    "M161.5";
      UN    "M161.3";
      O     "PZB";
      O     "SL434";
      ON    "M161.0";
      ON    "M145.2";
      S     "M161.2";
      R     "M161.4";
NETWORK
TITLE =Cont Rilascio Pulsante di Prenotazione Stop Ciclo Zona Bandiere

      UN    "PL435";
      U     "M161.2";
      S     "M161.3";
NETWORK
TITLE =Riavviamento Ciclo dopo Prenotazione Stop Ciclo Zona Bandiere

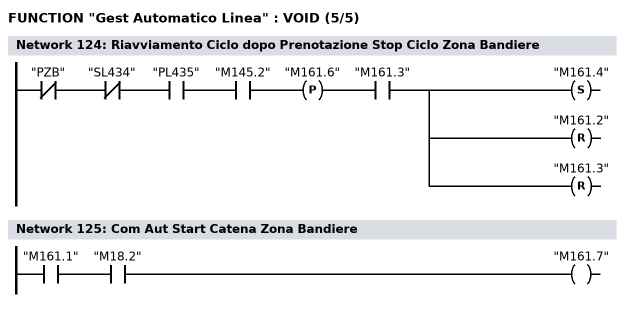
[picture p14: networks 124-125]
      UN    "PZB";
      UN    "SL434";
      U     "PL435";
      U     "M145.2";
      FP    "M161.6";
      U     "M161.3";
      S     "M161.4";
      R     "M161.2";
      R     "M161.3";
NETWORK
TITLE =Com Aut Start Catena Zona Bandiere

      U     "M161.1";
      U     "M18.2";
      =     "M161.7";
NETWORK
TITLE ========= Allineamento =======



NETWORK
TITLE =Presenza Pallet in arrivo Zona Bandiere

      U(    ;
      U(    ;
      UN    "SL710";
      U     "SL710B";
      O     "M218.0";
      )     ;
      U     "PX391";
      L     S5T#500MS;
      SE    T     24;
      NOP   0;
      NOP   0;
      NOP   0;
      U     T     24;
      )     ;
      L     S5T#2S;
      SA    T     25;
      NOP   0;
      NOP   0;
      NOP   0;
      U     T     25;
      =     "M162.0";
NETWORK
TITLE =Presenza Pallet Sotto Allinea Bandiere

      U(    ;
      U     "PX432";
      L     S5T#2S;
      SE    T     26;
      NOP   0;
      NOP   0;
      NOP   0;
      U     T     26;
      )     ;
      L     S5T#5S500MS;
      SA    T     27;
      NOP   0;
      NOP   0;
      NOP   0;
      U     T     27;
      =     "M162.1";
NETWORK
TITLE =Com Aut Salita Fermo Pallet in arrivo Zona Bandiere

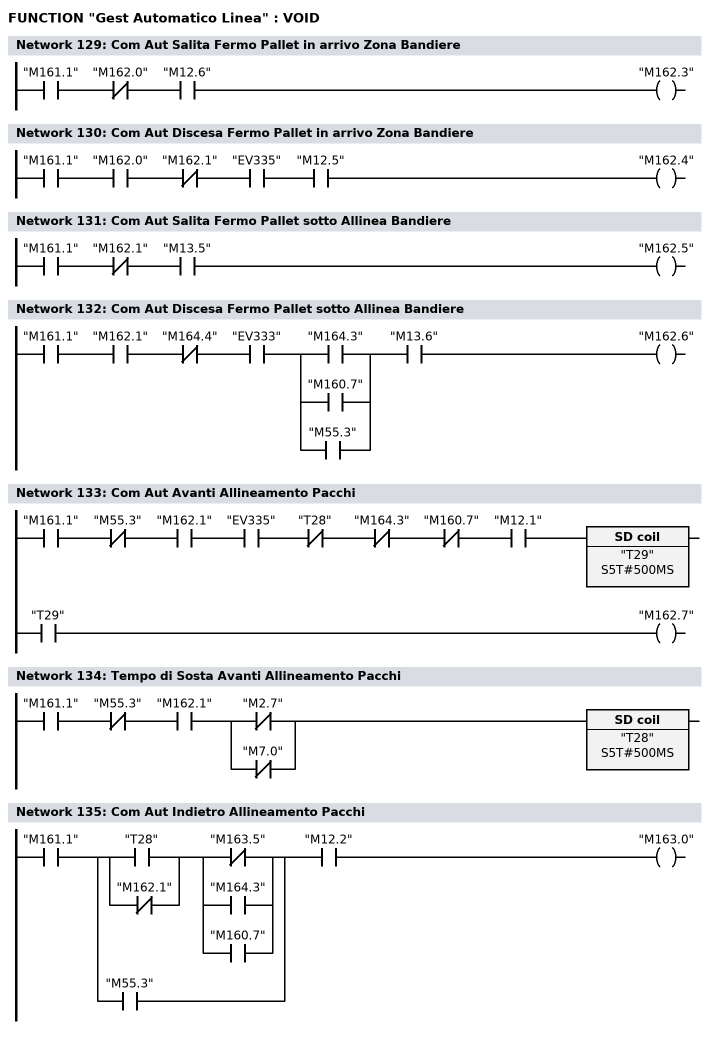
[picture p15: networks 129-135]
      U     "M161.1";
      UN    "M162.0";
      U     "M12.6";
      =     "M162.3";
NETWORK
TITLE =Com Aut Discesa Fermo Pallet in arrivo Zona Bandiere

      U     "M161.1";
      U     "M162.0";
      UN    "M162.1";
      U     "EV335";
      U     "M12.5";
      =     "M162.4";
NETWORK
TITLE =Com Aut Salita Fermo Pallet sotto Allinea Bandiere

      U     "M161.1";
      UN    "M162.1";
      U     "M13.5";
      =     "M162.5";
NETWORK
TITLE =Com Aut Discesa Fermo Pallet sotto Allinea Bandiere

      U     "M161.1";
      U     "M162.1";
      UN    "M164.4";
      U     "EV333";
      U(    ;
      O     "M164.3";
      O     "M160.7";
      O     "M55.3";
      )     ;
      U     "M13.6";
      =     "M162.6";
NETWORK
TITLE =Com Aut Avanti Allineamento Pacchi

      U     "M161.1";
      UN    "M55.3";
      U     "M162.1";
      U     "EV335";
      UN    "T28";
      UN    "M164.3";
      UN    "M160.7";
      U     "M12.1";
      L     S5T#500MS;
      SE    "T29";
      NOP   0;
      NOP   0;
      NOP   0;
      U     "T29";
      =     "M162.7";
NETWORK
TITLE =Tempo di Sosta Avanti Allineamento Pacchi

      U     "M161.1";
      UN    "M55.3";
      U     "M162.1";
      U(    ;
      ON    "M2.7";
      ON    "M7.0";
      )     ;
      L     S5T#500MS;
      SE    "T28";
      NOP   0;
      NOP   0;
      NOP   0;
      NOP   0;
NETWORK
TITLE =Com Aut Indietro Allineamento Pacchi

      U     "M161.1";
      U(    ;
      U(    ;
      O     "T28";
      ON    "M162.1";
      )     ;
      U(    ;
      ON    "M163.5";
      O     "M164.3";
      O     "M160.7";
      )     ;
      O     "M55.3";
      )     ;
      U     "M12.2";
      =     "M163.0";
NETWORK
TITLE =Numero di Colpi per l'Allineamento Pacchi

      U     "M161.1";
      UN    "M55.3";
      U     "M162.7";
      FP    M    247.0;
      ZR    Z      1;
      BLD   101;
      UN    "M162.1";
      L     DB98.DBW  166;
      S     Z      1;
      NOP   0;
      NOP   0;
      NOP   0;
      NOP   0;
NETWORK
TITLE =Numero Colpi per l'Allineamento Pacchi Eseguito

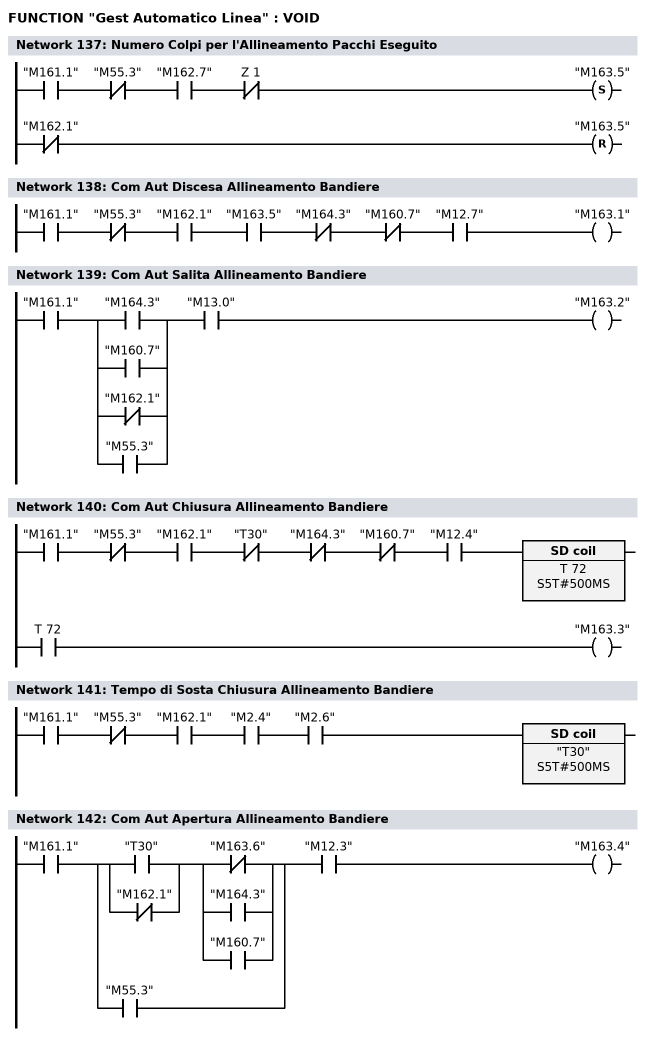
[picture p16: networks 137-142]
      U     "M161.1";
      UN    "M55.3";
      U     "M162.7";
      UN    Z      1;
      S     "M163.5";
      UN    "M162.1";
      R     "M163.5";
      NOP   0;
NETWORK
TITLE =Com Aut Discesa Allineamento Bandiere

      U     "M161.1";
      UN    "M55.3";
      U     "M162.1";
      U     "M163.5";
      UN    "M164.3";
      UN    "M160.7";
      U     "M12.7";
      =     "M163.1";
NETWORK
TITLE =Com Aut Salita Allineamento Bandiere

      U     "M161.1";
      U(    ;
      O     "M164.3";
      O     "M160.7";
      ON    "M162.1";
      O     "M55.3";
      )     ;
      U     "M13.0";
      =     "M163.2";
NETWORK
TITLE =Com Aut Chiusura Allineamento Bandiere

      U     "M161.1";
      UN    "M55.3";
      U     "M162.1";
      UN    "T30";
      UN    "M164.3";
      UN    "M160.7";
      U     "M12.4";
      L     S5T#500MS;
      SE    T     72;
      NOP   0;
      NOP   0;
      NOP   0;
      U     T     72;
      =     "M163.3";
NETWORK
TITLE =Tempo di Sosta Chiusura Allineamento Bandiere

      U     "M161.1";
      UN    "M55.3";
      U     "M162.1";
      U     "M2.4";
      U     "M2.6";
      L     S5T#500MS;
      SE    "T30";
      NOP   0;
      NOP   0;
      NOP   0;
      NOP   0;
NETWORK
TITLE =Com Aut Apertura Allineamento Bandiere

      U     "M161.1";
      U(    ;
      U(    ;
      O     "T30";
      ON    "M162.1";
      )     ;
      U(    ;
      ON    "M163.6";
      O     "M164.3";
      O     "M160.7";
      )     ;
      O     "M55.3";
      )     ;
      U     "M12.3";
      =     "M163.4";
NETWORK
TITLE =Numero di Colpi per l'Allineamento Bandiere

      U     "M161.1";
      UN    "M55.3";
      U     "M163.3";
      FP    M    247.1;
      ZR    Z      2;
      BLD   101;
      UN    "M162.1";
      L     DB98.DBW  168;
      S     Z      2;
      NOP   0;
      NOP   0;
      NOP   0;
      NOP   0;
NETWORK
TITLE =Numero Colpi per l'Allineamento Bandiere Eseguito

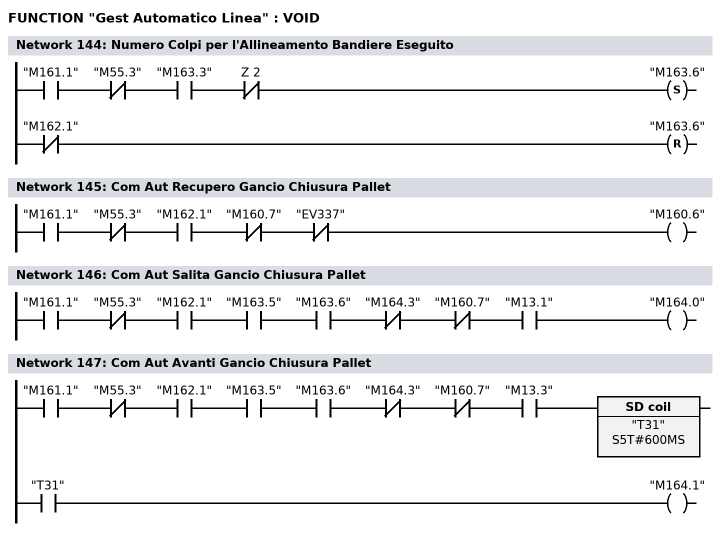
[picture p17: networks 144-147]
      U     "M161.1";
      UN    "M55.3";
      U     "M163.3";
      UN    Z      2;
      S     "M163.6";
      UN    "M162.1";
      R     "M163.6";
      NOP   0;
NETWORK
TITLE =Com Aut Recupero Gancio Chiusura Pallet

      U     "M161.1";
      UN    "M55.3";
      U     "M162.1";
      UN    "M160.7";
      UN    "EV337";
      =     "M160.6";
NETWORK
TITLE =Com Aut Salita Gancio Chiusura Pallet

      U     "M161.1";
      UN    "M55.3";
      U     "M162.1";
      U     "M163.5";
      U     "M163.6";
      UN    "M164.3";
      UN    "M160.7";
      U     "M13.1";
      =     "M164.0";
NETWORK
TITLE =Com Aut Avanti Gancio Chiusura Pallet

      U     "M161.1";
      UN    "M55.3";
      U     "M162.1";
      U     "M163.5";
      U     "M163.6";
      UN    "M164.3";
      UN    "M160.7";
      U     "M13.3";
      L     S5T#600MS;
      SE    "T31";
      NOP   0;
      NOP   0;
      NOP   0;
      U     "T31";
      =     "M164.1";
NETWORK
TITLE =Com Aut Discesa Gancio Chiusura Pallet

      U(    ;
      U     "M161.1";
      U(    ;
      U     "M162.1";
      U     "M163.5";
      U     "M163.6";
      U     "M13.2";
      O     "M55.3";
      )     ;
      L     S5T#2S;
      SE    T     73;
      NOP   0;
      NOP   0;
      NOP   0;
      U     T     73;
      )     ;
      S     "M164.2";
      U     "M160.7";
      R     "M164.2";
      NOP   0;
NETWORK
TITLE =Com Aut Indietro Chiusura Pallet

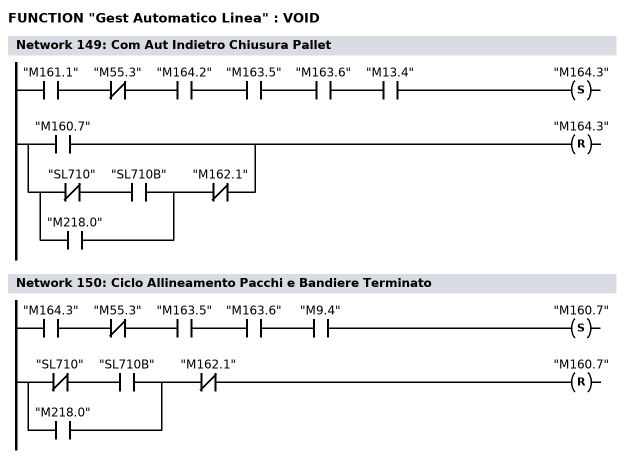
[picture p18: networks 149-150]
      U     "M161.1";
      UN    "M55.3";
      U     "M164.2";
      U     "M163.5";
      U     "M163.6";
      U     "M13.4";
      S     "M164.3";
      U(    ;
      O     "M160.7";
      O     ;
      U(    ;
      UN    "SL710";
      U     "SL710B";
      O     "M218.0";
      )     ;
      UN    "M162.1";
      )     ;
      R     "M164.3";
      NOP   0;
NETWORK
TITLE =Ciclo Allineamento Pacchi e Bandiere Terminato

      U     "M164.3";
      UN    "M55.3";
      U     "M163.5";
      U     "M163.6";
      U     "M9.4";
      S     "M160.7";
      U(    ;
      UN    "SL710";
      U     "SL710B";
      O     "M218.0";
      )     ;
      UN    "M162.1";
      R     "M160.7";
      NOP   0;
NETWORK
TITLE ========= Piegatura =======



NETWORK
TITLE =Presenza Pallet Fermo Pallet in Arrivo Zona Piegatura

      U(    ;
      U(    ;
      UN    "SL710";
      U     "SL710B";
      O     "M218.0";
      )     ;
      U     "PX393";
      L     S5T#500MS;
      SE    T     32;
      NOP   0;
      NOP   0;
      NOP   0;
      U     T     32;
      )     ;
      L     S5T#2S;
      SA    T     33;
      NOP   0;
      NOP   0;
      NOP   0;
      U     T     33;
      =     "M164.4";
NETWORK
TITLE =Presenza Pallet sotto la Zona Piegatura

      U(    ;
      U     "PX395";
      L     S5T#2S;
      SE    T     37;
      NOP   0;
      NOP   0;
      NOP   0;
      U     T     37;
      )     ;
      L     S5T#500MS;
      SA    T     38;
      NOP   0;
      NOP   0;
      NOP   0;
      U     T     38;
      =     "M164.5";
NETWORK
TITLE =Presenza Pallet in uscita dalla Zona Piegatura

      U(    ;
      U(    ;
      UN    "SL710";
      U     "SL710B";
      O     "M218.0";
      )     ;
      U     "PX397";
      L     S5T#2S;
      SE    T     39;
      NOP   0;
      NOP   0;
      NOP   0;
      U     T     39;
      )     ;
      L     S5T#3S;
      SA    T     40;
      NOP   0;
      NOP   0;
      NOP   0;
      U     T     40;
      =     "M164.6";
NETWORK
TITLE =Presenza Primo Pallet su Fermo Pallet Zona Ascensore C.O.S.

      U(    ;
      U(    ;
      UN    "SL710";
      U     "SL710B";
      O     "M218.0";
      )     ;
      U     "PX401";
      L     S5T#2S;
      SE    T     41;
      NOP   0;
      NOP   0;
      NOP   0;
      U     T     41;
      )     ;
      L     S5T#10S;
      SA    T     42;
      NOP   0;
      NOP   0;
      NOP   0;
      U     T     42;
      =     "M164.7";
NETWORK
TITLE =Presenza Secondo Pallet su Fermo Pallet Zona Ascensore C.O.S.

      U(    ;
      U(    ;
      UN    "SL710";
      U     "SL710B";
      O     "M218.0";
      )     ;
      U     "PX433";
      L     S5T#2S;
      SE    T     43;
      NOP   0;
      NOP   0;
      NOP   0;
      U     T     43;
      )     ;
      L     S5T#10S;
      SA    T     44;
      NOP   0;
      NOP   0;
      NOP   0;
      U     T     44;
      =     "M165.0";
NETWORK
TITLE =Com Aut Salita Fermo Pallet in Arrivo Zona Piegatura Bandiere

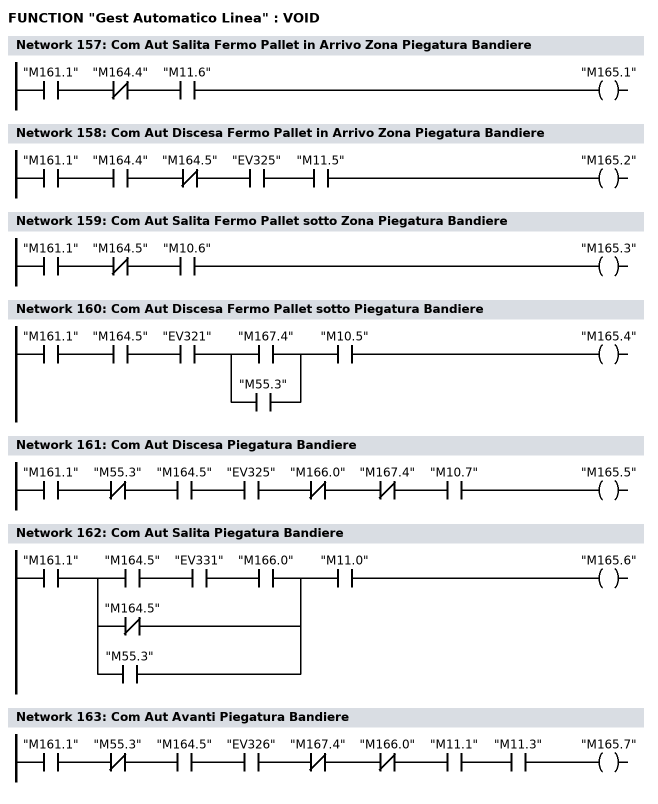
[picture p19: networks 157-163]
      U     "M161.1";
      UN    "M164.4";
      U     "M11.6";
      =     "M165.1";
NETWORK
TITLE =Com Aut Discesa Fermo Pallet in Arrivo Zona Piegatura Bandiere

      U     "M161.1";
      U     "M164.4";
      UN    "M164.5";
      U     "EV325";
      U     "M11.5";
      =     "M165.2";
NETWORK
TITLE =Com Aut Salita Fermo Pallet sotto Zona Piegatura Bandiere

      U     "M161.1";
      UN    "M164.5";
      U     "M10.6";
      =     "M165.3";
NETWORK
TITLE =Com Aut Discesa Fermo Pallet sotto Piegatura Bandiere

      U     "M161.1";
      U     "M164.5";
      U     "EV321";
      U(    ;
      O     "M167.4";
      O     "M55.3";
      )     ;
      U     "M10.5";
      =     "M165.4";
NETWORK
TITLE =Com Aut Discesa Piegatura Bandiere

      U     "M161.1";
      UN    "M55.3";
      U     "M164.5";
      U     "EV325";
      UN    "M166.0";
      UN    "M167.4";
      U     "M10.7";
      =     "M165.5";
NETWORK
TITLE =Com Aut Salita Piegatura Bandiere

      U     "M161.1";
      U(    ;
      U     "M164.5";
      U     "EV331";
      U     "M166.0";
      ON    "M164.5";
      O     "M55.3";
      )     ;
      U     "M11.0";
      =     "M165.6";
NETWORK
TITLE =Com Aut Avanti Piegatura Bandiere

      U     "M161.1";
      UN    "M55.3";
      U     "M164.5";
      U     "EV326";
      UN    "M167.4";
      UN    "M166.0";
      U     "M11.1";
      U     "M11.3";
      =     "M165.7";
NETWORK
TITLE =Com Aut Indietro Piegatura Bandiere

      U(    ;
      U     "M161.1";
      U     "M11.2";
      U     "M11.4";
      L     S5T#2S;
      SE    T     45;
      NOP   0;
      NOP   0;
      NOP   0;
      U     T     45;
      )     ;
      S     "M166.0";
      U(    ;
      O     "M167.4";
      O     ;
      U     "M166.0";
      UN    "M164.5";
      U     "M8.0";
      U     "M8.1";
      )     ;
      R     "M166.0";
      NOP   0;
NETWORK
TITLE =Fine Ciclo Piegatura

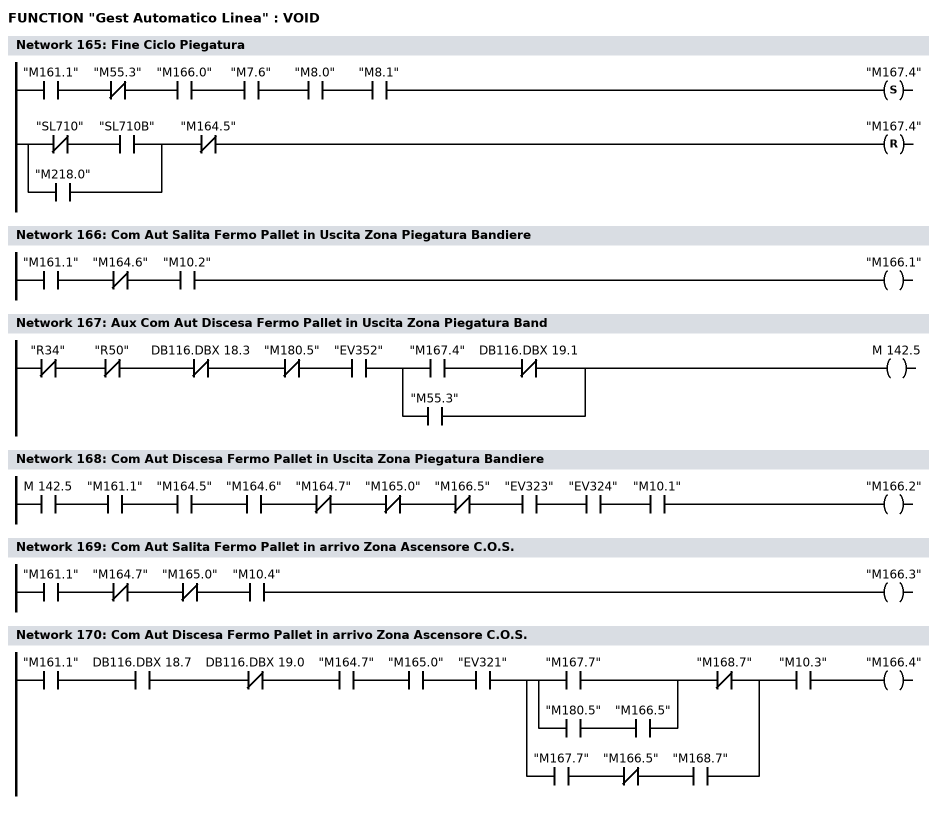
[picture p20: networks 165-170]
      U     "M161.1";
      UN    "M55.3";
      U     "M166.0";
      U     "M7.6";
      U     "M8.0";
      U     "M8.1";
      S     "M167.4";
      U(    ;
      UN    "SL710";
      U     "SL710B";
      O     "M218.0";
      )     ;
      UN    "M164.5";
      R     "M167.4";
      NOP   0;
NETWORK
TITLE =Com Aut Salita Fermo Pallet in Uscita Zona Piegatura Bandiere

      U     "M161.1";
      UN    "M164.6";
      U     "M10.2";
      =     "M166.1";
NETWORK
TITLE =Aux Com Aut Discesa Fermo Pallet in Uscita Zona Piegatura Band

      UN    "R34";
      UN    "R50";
      UN    DB116.DBX   18.3;
      UN    "M180.5";
      U     "EV352";
      U(    ;
      U     "M167.4";
      UN    DB116.DBX   19.1;
      O     "M55.3";
      )     ;
      =     M    142.5;
NETWORK
TITLE =Com Aut Discesa Fermo Pallet in Uscita Zona Piegatura Bandiere

      U     M    142.5;
      U     "M161.1";
      U     "M164.5";
      U     "M164.6";
      UN    "M164.7";
      UN    "M165.0";
      UN    "M166.5";
      U     "EV323";
      U     "EV324";
      U     "M10.1";
      =     "M166.2";
NETWORK
TITLE =Com Aut Salita Fermo Pallet in arrivo Zona Ascensore C.O.S.

      U     "M161.1";
      UN    "M164.7";
      UN    "M165.0";
      U     "M10.4";
      =     "M166.3";
NETWORK
TITLE =Com Aut Discesa Fermo Pallet in arrivo Zona Ascensore C.O.S.

      U     "M161.1";
      U     DB116.DBX   18.7;
      UN    DB116.DBX   19.0;
      U     "M164.7";
      U     "M165.0";
      U     "EV321";
      U(    ;
      U(    ;
      O     "M167.7";
      O     ;
      U     "M180.5";
      U     "M166.5";
      )     ;
      UN    "M168.7";
      O     ;
      U     "M167.7";
      UN    "M166.5";
      U     "M168.7";
      )     ;
      U     "M10.3";
      =     "M166.4";
NETWORK
TITLE ======== Ascensore C.O.S. Ciclo Ascensore Comandi da Linea ======



NETWORK
TITLE =Presenza Pallet sull'ascensore

      U(    ;
      U     "PX690";
      L     S5T#1S;
      SA    T     47;
      NOP   0;
      NOP   0;
      NOP   0;
      U     T     47;
      )     ;
      L     S5T#1S500MS;
      SE    T     46;
      NOP   0;
      NOP   0;
      NOP   0;
      U     T     46;
      =     "M166.5";
NETWORK
TITLE =Com Aut Salita Fermo Pallet Anteriore su Ascensore C.O.S.

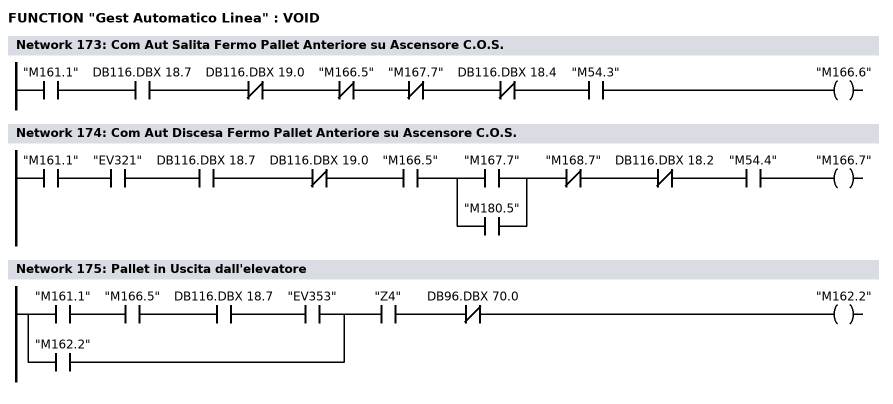
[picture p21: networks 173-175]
      U     "M161.1";
      U     DB116.DBX   18.7;
      UN    DB116.DBX   19.0;
      UN    "M166.5";
      UN    "M167.7";
      UN    DB116.DBX   18.4;
      U     "M54.3";
      =     "M166.6";
NETWORK
TITLE =Com Aut Discesa Fermo Pallet Anteriore su Ascensore C.O.S.

      U     "M161.1";
      U     "EV321";
      U     DB116.DBX   18.7;
      UN    DB116.DBX   19.0;
      U     "M166.5";
      U(    ;
      O     "M167.7";
      O     "M180.5";
      )     ;
      UN    "M168.7";
      UN    DB116.DBX   18.2;
      U     "M54.4";
      =     "M166.7";
NETWORK
TITLE =Pallet in Uscita dall'elevatore

      U(    ;
      U     "M161.1";
      U     "M166.5";
      U     DB116.DBX   18.7;
      U     "EV353";
      O     "M162.2";
      )     ;
      U     "Z4";
      UN    DB96.DBX   70.0;
      =     "M162.2";
NETWORK
TITLE =Conteggio Pattini Pallet in Uscita dall'elevatore

      U     "M162.2";
      U     "E      68.3";
      ZR    "Z4";
      BLD   101;
      U     "EV352";
      U(    ;
      ON    "Z4";
      O     ;
      U     DB96.DBX   70.0;
      U     "PL716";
      )     ;
      L     C#6;
      S     "Z4";
      NOP   0;
      NOP   0;
      NOP   0;
      NOP   0;
NETWORK
TITLE =Com Aut Salita Fermo Pallet Posteriore su Ascensore C.O.S.

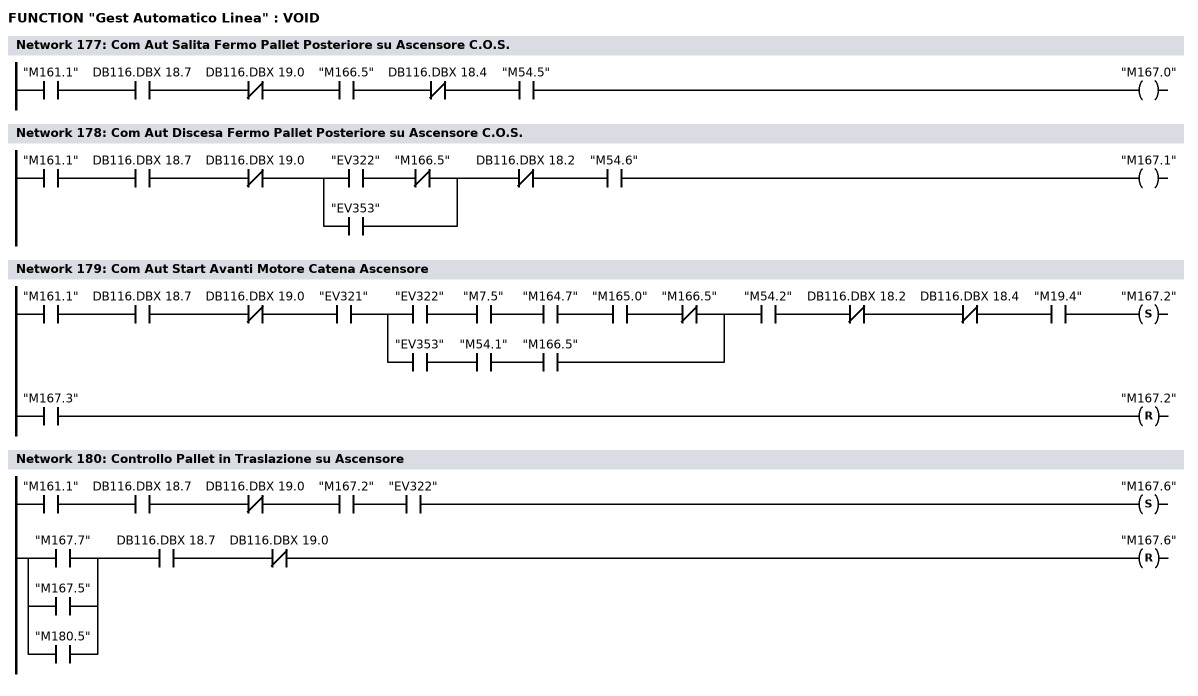
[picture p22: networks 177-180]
      U     "M161.1";
      U     DB116.DBX   18.7;
      UN    DB116.DBX   19.0;
      U     "M166.5";
      UN    DB116.DBX   18.4;
      U     "M54.5";
      =     "M167.0";
NETWORK
TITLE =Com Aut Discesa Fermo Pallet Posteriore su Ascensore C.O.S.

      U     "M161.1";
      U     DB116.DBX   18.7;
      UN    DB116.DBX   19.0;
      U(    ;
      U     "EV322";
      UN    "M166.5";
      O     "EV353";
      )     ;
      UN    DB116.DBX   18.2;
      U     "M54.6";
      =     "M167.1";
NETWORK
TITLE =Com Aut Start Avanti Motore Catena Ascensore

      U     "M161.1";
      U     DB116.DBX   18.7;
      UN    DB116.DBX   19.0;
      U     "EV321";
      U(    ;
      U     "EV322";
      U     "M7.5";
      U     "M164.7";
      U     "M165.0";
      UN    "M166.5";
      O     ;
      U     "EV353";
      U     "M54.1";
      U     "M166.5";
      )     ;
      U     "M54.2";
      UN    DB116.DBX   18.2;
      UN    DB116.DBX   18.4;
      U     "M19.4";
      S     "M167.2";
      U     "M167.3";
      R     "M167.2";
      NOP   0;
NETWORK
TITLE =Controllo Pallet in Traslazione su Ascensore

      U     "M161.1";
      U     DB116.DBX   18.7;
      UN    DB116.DBX   19.0;
      U     "M167.2";
      U     "EV322";
      S     "M167.6";
      U(    ;
      O     "M167.7";
      O     "M167.5";
      O     "M180.5";
      )     ;
      U     DB116.DBX   18.7;
      UN    DB116.DBX   19.0;
      R     "M167.6";
      NOP   0;
NETWORK
TITLE =Com Aut Start Indietro Motore Ascensore

      U(    ;
      U     "M161.1";
      U     DB116.DBX   18.7;
      UN    DB116.DBX   19.0;
      U     "M167.2";
      U(    ;
      U     "M166.5";
      U     "M167.6";
      UN    "M54.2";
      O     ;
      UN    "M166.5";
      UN    "M167.6";
      UN    "M164.7";
      UN    "M165.0";
      )     ;
      U     "EV352";
      U     "M19.4";
      L     S5T#500MS;
      SE    "T48";
      NOP   0;
      NOP   0;
      NOP   0;
      U     "T48";
      )     ;
      S     "M167.3";
      U(    ;
      O     "T49";
      O     "M167.5";
      )     ;
      R     "M167.3";
      NOP   0;
NETWORK
TITLE =Tempo di Inversione Catena Ascensore C.O.S.

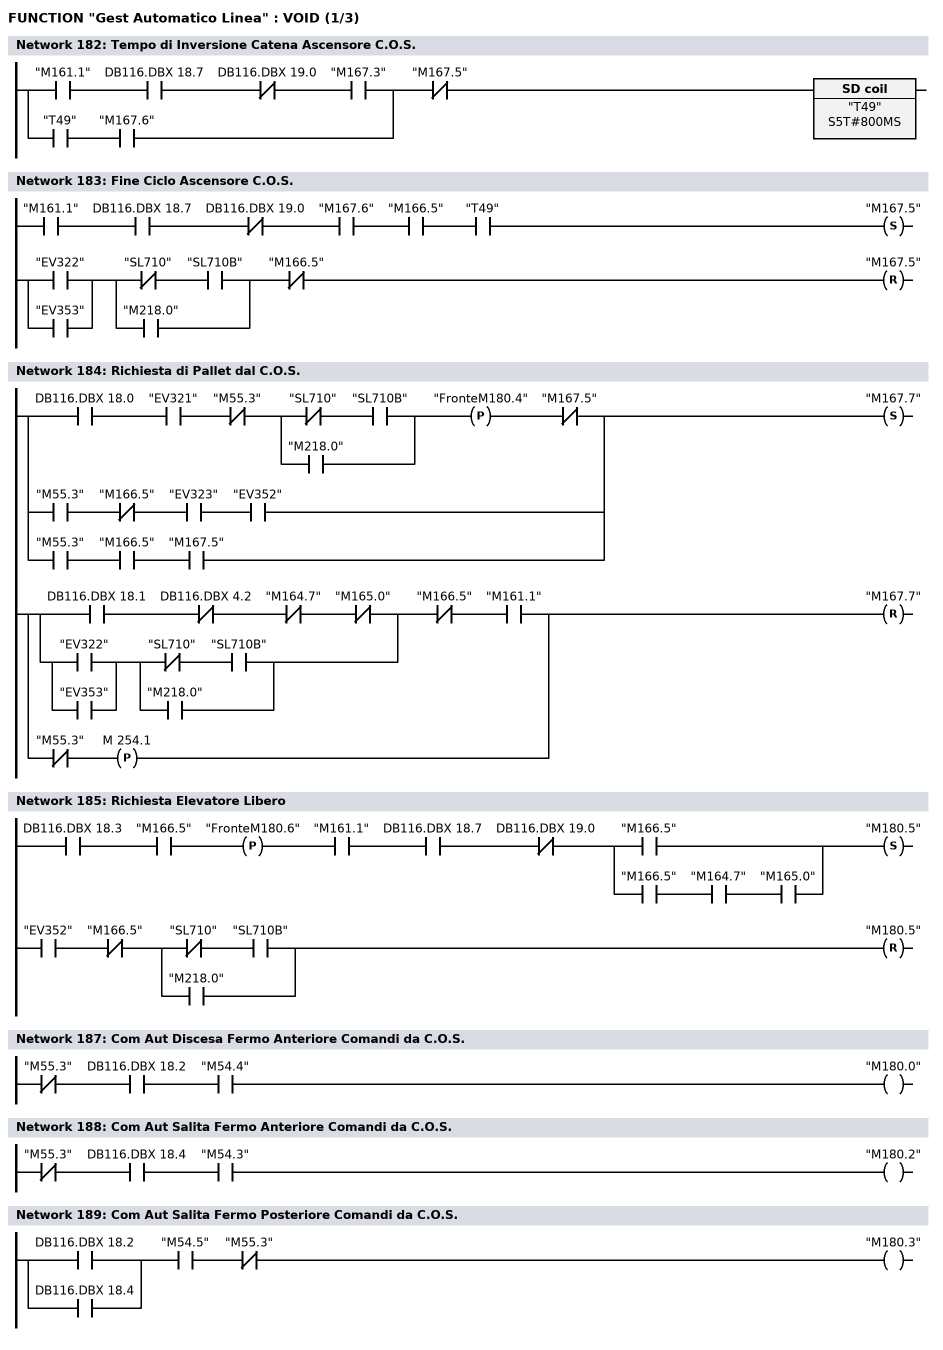
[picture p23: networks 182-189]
      U(    ;
      U     "M161.1";
      U     DB116.DBX   18.7;
      UN    DB116.DBX   19.0;
      U     "M167.3";
      O     ;
      U     "T49";
      U     "M167.6";
      )     ;
      UN    "M167.5";
      L     S5T#800MS;
      SE    "T49";
      NOP   0;
      NOP   0;
      NOP   0;
      NOP   0;
NETWORK
TITLE =Fine Ciclo Ascensore C.O.S.

      U     "M161.1";
      U     DB116.DBX   18.7;
      UN    DB116.DBX   19.0;
      U     "M167.6";
      U     "M166.5";
      U     "T49";
      S     "M167.5";
      U(    ;
      O     "EV322";
      O     "EV353";
      )     ;
      U(    ;
      UN    "SL710";
      U     "SL710B";
      O     "M218.0";
      )     ;
      UN    "M166.5";
      R     "M167.5";
      NOP   0;
NETWORK
TITLE =Richiesta di Pallet dal C.O.S.

      U(    ;
      U     DB116.DBX   18.0;
      U     "EV321";
      UN    "M55.3";
      U(    ;
      UN    "SL710";
      U     "SL710B";
      O     "M218.0";
      )     ;
      FP    "FronteM180.4";
      UN    "M167.5";
      O     ;
      U     "M55.3";
      UN    "M166.5";
      U     "EV323";
      U     "EV352";
      O     ;
      U     "M55.3";
      U     "M166.5";
      U     "M167.5";
      )     ;
      S     "M167.7";
      U(    ;
      U(    ;
      U     DB116.DBX   18.1;
      UN    DB116.DBX    4.2;
      UN    "M164.7";
      UN    "M165.0";
      O     ;
      U(    ;
      O     "EV322";
      O     "EV353";
      )     ;
      U(    ;
      UN    "SL710";
      U     "SL710B";
      O     "M218.0";
      )     ;
      )     ;
      UN    "M166.5";
      U     "M161.1";
      O(    ;
      UN    "M55.3";
      FP    M    254.1;
      )     ;
      )     ;
      R     "M167.7";
      NOP   0;
NETWORK
TITLE =Richiesta Elevatore Libero

      U     DB116.DBX   18.3;
      U     "M166.5";
      FP    "FronteM180.6";
      U     "M161.1";
      U     DB116.DBX   18.7;
      UN    DB116.DBX   19.0;
      U(    ;
      O     "M166.5";
      O     ;
      U     "M166.5";
      U     "M164.7";
      U     "M165.0";
      )     ;
      S     "M180.5";
      U     "EV352";
      UN    "M166.5";
      U(    ;
      UN    "SL710";
      U     "SL710B";
      O     "M218.0";
      )     ;
      R     "M180.5";
      NOP   0;
NETWORK
TITLE ======== Ascensore C.O.S. Ciclo Ascensore Comandi da C.O.S. =====



NETWORK
TITLE =Com Aut Discesa Fermo Anteriore Comandi da C.O.S.

      UN    "M55.3";
      U     DB116.DBX   18.2;
      U     "M54.4";
      =     "M180.0";
NETWORK
TITLE =Com Aut Salita Fermo Anteriore Comandi da C.O.S.

      UN    "M55.3";
      U     DB116.DBX   18.4;
      U     "M54.3";
      =     "M180.2";
NETWORK
TITLE =Com Aut Salita Fermo Posteriore Comandi da C.O.S.

      U(    ;
      O     DB116.DBX   18.2;
      O     DB116.DBX   18.4;
      )     ;
      U     "M54.5";
      UN    "M55.3";
      =     "M180.3";
NETWORK
TITLE ======== Ciclo Automatico parte Finale Linea =======



NETWORK
TITLE =Condizioni per Ciclo parte Finale Linea

      U     "MG";
      U     "E4.2";
      UN    "M25.5";
      UN    "SL680";
      UN    "PBoxingDX";
      U     "PR637";
      =     "M168.0";
NETWORK
TITLE =Nessun Allarme Presente Zona Apertura e Scarico

      U(    ;
      L     DB96.DBD   76;
      L     L#0;
      ==D   ;
      )     ;
      U(    ;
      L     DB96.DBD   80;
      L     L#0;
      ==D   ;
      )     ;
      U(    ;
      L     DB96.DBW   84;
      L     0;
      ==I   ;
      )     ;
      =     "M145.3";
NETWORK
TITLE =Start Ciclo Automatico parte Finale Linea

      U(    ;
      O     "PL712";
      O     "M168.4";
      O     "M168.1";
      )     ;
      U     "M168.0";
      UN    "M168.2";
      =     "M168.1";
NETWORK
TITLE =Prenotazione Stop Ciclo parte Finale Linea

      U(    ;
      O     "PL682";
      O     "PL732";
      O     ;
      UN    "PL713";
      UN    "M218.0";
      )     ;
      FP    "M168.5";
      UN    "M168.3";
      O     "SL680";
      O     "SL681";
      O     "PBoxingDX";
      O     "SL731";
      ON    "M168.0";
      ON    "M145.3";
      ON    "M145.4";
      ON    "M145.5";
      ON    "M145.6";
      O     ;
      U     "M55.4";
      U     "FT632";
      U     "M8.7";
      S     "M168.2";
      R     "M168.4";
NETWORK
TITLE =Cont Rilascio Pulsante di Prenotaz Stop Ciclo parte Finale Linea

      UN    "PL682";
      UN    "PL732";
      U     "M168.2";
      S     "M168.3";
NETWORK
TITLE =Riavviamento Ciclo dopo Prenotaz Stop Ciclo parte Finale Linea

      UN    "SL680";
      UN    "SL681";
      UN    "PBoxingDX";
      UN    "SL731";
      U     "M145.3";
      U     "M145.4";
      U     "M145.5";
      U     "M145.6";
      U(    ;
      ON    "M55.4";
      O     ;
      U     "M55.4";
      UN    "FT632";
      )     ;
      U(    ;
      O     "PL682";
      O     "PL732";
      )     ;
      FP    "M168.6";
      U     "M168.3";
      S     "M168.4";
      R     "M168.2";
      R     "M168.3";
NETWORK
TITLE ======== Zona Apertura Pallet =======



NETWORK
TITLE =Troppo pieno su Apertura Pallet

      U(    ;
      UN    "SL710";
      U     "SL710B";
      O     "M218.0";
      )     ;
      U     "PX633";
      L     S5T#2S;
      SE    "T53";
      NOP   0;
      NOP   0;
      NOP   0;
      U     "T53";
      =     "M168.7";
NETWORK
TITLE =Presenza Pallet in Zona Apertura Pallet

      U     "PX635";
      L     S5T#2S;
      SE    "T55";
      NOP   0;
      NOP   0;
      NOP   0;
      U     "T55";
      =     "M169.0";
NETWORK
TITLE =Presenza Pallet sul Fermo in Arrivo Zona Scarico

      U(    ;
      U     "PX650";
      L     S5T#1S;
      SE    T    123;
      NOP   0;
      NOP   0;
      NOP   0;
      U     T    123;
      )     ;
      L     S5T#3S500MS;
      SA    T    124;
      NOP   0;
      NOP   0;
      NOP   0;
      U     T    124;
      =     "M173.1";
NETWORK
TITLE =Com Aut Start Motore Catena Zona Apertura Pallet

      U     "M168.1";
      U     "M18.3";
      =     "M169.1";
NETWORK
TITLE =Com Aut Avanti Fermo Pallet in Arrivo Zona Apertura Pallet

      U     "M168.1";
      U     "M169.0";
      U     "M14.5";
      =     "M169.2";
NETWORK
TITLE =Com Aut Indietro Fermo Pallet in Arrivo Zona Apertura Pallet

      U     "M168.1";
      UN    "M169.0";
      U     "EV614";
      U     "M14.5";
      =     "M169.3";
NETWORK
TITLE =Com Aut Salita Fermo Pallet su Zona Apertura Pallet

      U     "M168.1";
      UN    "M169.0";
      U     "M173.1";
      U     "R24";
      U     "EV615";
      U     "M14.7";
      =     "M169.4";
NETWORK
TITLE =Com Aut Discesa Fermo Pallet su Zona Apertura Pallet

      U     "M168.1";
      U     "M169.0";
      U(    ;
      O     "M170.6";
      O     "M55.3";
      )     ;
      UN    "M173.1";
      U     "M15.0";
      =     "M169.5";
NETWORK
TITLE =Com Aut Discesa Bloccaggio Pallet

      U     "M168.1";
      UN    "M55.3";
      U     "EV614";
      U     "M169.0";
      UN    "M170.6";
      =     "M169.6";
NETWORK
TITLE =Com Aut Salita Bloccaggio Pallet

      U     "M168.1";
      U(    ;
      ON    "M169.0";
      O     "M170.6";
      O     "M55.3";
      )     ;
      =     "M169.7";
NETWORK
TITLE =Com Aut Salita Gangio Apertura Pallet

      U     "M168.1";
      UN    "M55.3";
      U     "EV645";
      UN    "M14.0";
      U     "M13.7";
      UN    "M170.6";
      U     "M15.1";
      L     S5T#500MS;
      SE    "T57";
      NOP   0;
      NOP   0;
      NOP   0;
      U     "T57";
      =     "M170.0";
NETWORK
TITLE =Com Aut Discesa Gancio e Dente Apertura Pallet

      U     "M168.1";
      U(    ;
      O     "M14.1";
      ON    "M169.0";
      O     "M55.3";
      )     ;
      U     "M15.2";
      L     S5T#500MS;
      SE    "T70";
      NOP   0;
      NOP   0;
      NOP   0;
      U     "T70";
      =     "M170.1";
NETWORK
TITLE =Com Aut Salita Dente Apertura Pallet

      U     "M168.1";
      UN    "M55.3";
      U     "EV441";
      U     "M137.0";
      U     "M13.7";
      UN    "M170.6";
      U     "M15.3";
      =     "M170.2";
NETWORK
TITLE =Com Aut Avanti Apertura Pallet

      U     "M168.1";
      UN    "M55.3";
      U     "M169.0";
      UN    "M14.1";
      UN    "M170.5";
      UN    "M170.6";
      U     "M15.7";
      L     S5T#1S;
      SE    T     59;
      NOP   0;
      NOP   0;
      NOP   0;
      U     T     59;
      =     "M170.4";
NETWORK
TITLE =Com Aut Indietro Apertura Pallet

      U     "M168.1";
      U(    ;
      U     "M169.0";
      U     "M137.0";
      U     "M9.7";
      U     "EV640";
      O     ;
      UN    "M13.7";
      U     "M16.0";
      U     "EV641";
      )     ;
      L     S5T#250MS;
      SA    T     69;
      NOP   0;
      NOP   0;
      NOP   0;
      U     T     69;
      =     "M170.5";
NETWORK
TITLE =Ciclo Apertura Pallet Terminato

      U     "M170.5";
      UN    "M55.3";
      U     "M9.6";
      U     "M9.7";
      FP    "M170.7";
      S     "M170.6";
      U(    ;
      UN    "SL710";
      U     "SL710B";
      O     "M218.0";
      )     ;
      UN    "M169.0";
      R     "M170.6";
      NOP   0;
NETWORK
TITLE =Com Aut Avanti Fermo in Arrivo Zona Scarico

      U     "M168.1";
      UN    "M173.1";
      =     "M173.2";
NETWORK
TITLE =Com Aut Indietro Fermo in Arrivo Zona Scarico

      U     "M168.1";
      UN    "M58.7";
      U     "M173.1";
      UN    "M171.0";
      U(    ;
      U     "EV604";
      UN    "M173.0";
      UN    "M175.0";
      O     "M175.1";
      )     ;
      U(    ;
      U     DB98.DBX  193.1;
      U     DB98.DBX  193.2;
      UN    "M171.1";
      UN    "M171.2";
      O     ;
      U(    ;
      ON    "M175.0";
      O     "M175.1";
      )     ;
      U     DB98.DBX  193.2;
      UN    "M171.1";
      U(    ;
      O     "M171.2";
      ON    DB98.DBX  193.1;
      )     ;
      O     ;
      U(    ;
      ON    "M173.0";
      O     "M175.1";
      )     ;
      U     DB98.DBX  193.1;
      U(    ;
      O     "M171.1";
      ON    DB98.DBX  193.2;
      )     ;
      UN    "M171.2";
      )     ;
      =     "M173.3";
NETWORK
TITLE ======== Zona Scarico Pallet =======



NETWORK
TITLE =Presenza Pallet in Arrivo su Traslatori Scarico Pallet

      U(    ;
      UN    "SL710";
      U     "SL710B";
      O     "M218.0";
      )     ;
      U     "PX627";
      L     S5T#1S;
      SE    T     60;
      NOP   0;
      NOP   0;
      NOP   0;
      U     T     60;
      =     "M171.0";
NETWORK
TITLE =Presenza Pallet su Traslatore Scarico Pallet SX

      U(    ;
      UN    "M55.3";
      U(    ;
      UN    "SL710";
      U     "SL710B";
      O     "M218.0";
      )     ;
      U(    ;
      O     "PX622";
      O     ;
      U     "M171.1";
      U     "EV607";
      U     "EV601";
      )     ;
      L     S5T#100MS;
      SE    T     61;
      NOP   0;
      NOP   0;
      NOP   0;
      U     T     61;
      )     ;
      L     S5T#1S500MS;
      SA    T     50;
      NOP   0;
      NOP   0;
      NOP   0;
      U     T     50;
      =     "M171.1";
NETWORK
TITLE =Presenza Pallet su Traslatore Scarico Pallet DX

      U(    ;
      UN    "M55.3";
      U(    ;
      UN    "SL710";
      U     "SL710B";
      O     "M218.0";
      )     ;
      U(    ;
      O     "PX625";
      O     ;
      U     "M171.2";
      U     "EV611";
      U     "EV603";
      )     ;
      L     S5T#100MS;
      SE    T     62;
      NOP   0;
      NOP   0;
      NOP   0;
      U     T     62;
      )     ;
      L     S5T#1S500MS;
      SA    T     63;
      NOP   0;
      NOP   0;
      NOP   0;
      U     T     63;
      =     "M171.2";
NETWORK
TITLE =Presenza Pallet su Traslatore Finale

      U(    ;
      UN    "SL710";
      U     "SL710B";
      O     "M218.0";
      )     ;
      U     "R24";
      U     "FT631";
      L     S5T#1S;
      SE    T     67;
      NOP   0;
      NOP   0;
      NOP   0;
      U     T     67;
      =     "M171.3";
NETWORK
TITLE =Presenza Pallet a Inizio Linea

      U(    ;
      UN    "SL710";
      U     "SL710B";
      O     "M218.0";
      )     ;
      U     "FT632";
      L     S5T#700MS;
      SE    T     68;
      NOP   0;
      NOP   0;
      NOP   0;
      U     T     68;
      =     "M171.4";
NETWORK
TITLE =Com Aut Start Catena Zona Scarico Pallet

      U     "M168.1";
      U     "M18.4";
      =     "M171.5";
NETWORK
TITLE =Com Aut Salita Fermo Pallet su Arrivo Traslatori Finali

      U     "M168.1";
      U(    ;
      UN    "M55.3";
      UN    "M55.4";
      UN    "M173.0";
      UN    "M175.0";
      O     ;
      U(    ;
      O     "M55.3";
      O     "M55.4";
      )     ;
      U     "M171.3";
      U     "R24";
      )     ;
      UN    "M171.0";
      U     "M16.5";
      =     "M171.6";
NETWORK
TITLE =Com Aut Discesa Fermo Pallet su Arrivo Traslatori Finali

      U     "M168.1";
      U(    ;
      UN    "M173.0";
      UN    "M8.4";
      UN    "M171.2";
      UN    "M175.0";
      O     ;
      UN    "M175.0";
      UN    "M8.2";
      UN    "M171.1";
      U     "M171.2";
      O     "M173.0";
      O     "M175.0";
      O     ;
      U(    ;
      O     "M55.3";
      O     "M55.4";
      )     ;
      UN    "M171.3";
      U     "M8.7";
      )     ;
      U     "M171.0";
      U     "M16.6";
      =     "M171.7";
NETWORK
TITLE =Com Aut Salita Traslatore di Scarico DX

      U     "M168.1";
      UN    "M55.3";
      UN    "M55.4";
      U     DB98.DBX  193.1;
      U(    ;
      UN    "M173.0";
      U     "M171.0";
      UN    "M171.2";
      UN    "M175.0";
      O     ;
      U     "M173.0";
      UN    "M171.0";
      U     "M171.2";
      U     "EV601";
      )     ;
      U     "M16.3";
      =     "M172.0";
NETWORK
TITLE =Com Aut Discesa Traslatore di Scarico DX

      U     "M168.1";
      U(    ;
      U     DB98.DBX  193.1;
      U(    ;
      UN    "M173.0";
      UN    "M171.0";
      U     "M171.2";
      U     "EV611";
      O     ;
      U     "M173.0";
      U     "M171.0";
      )     ;
      O     "M55.3";
      O     "M55.4";
      )     ;
      U     "M16.4";
      =     "M172.1";
NETWORK
TITLE =Com Aut Start Avanti Catena Traslatore DX

      U     "M168.1";
      U     DB98.DBX  193.1;
      UN    "M55.3";
      UN    "M55.4";
      UN    "M173.0";
      UN    "M171.2";
      U     "EV602";
      U     "M19.5";
      =     "M172.2";
NETWORK
TITLE =Com Aut Start Indietro Catena Traslatore DX

      U     "M168.1";
      U     DB98.DBX  193.1;
      UN    "M55.3";
      UN    "M55.4";
      U     "M173.0";
      UN    "M171.0";
      U     "EV602";
      U     "M19.5";
      =     "M172.3";
NETWORK
TITLE =Com Aut Bloccaggio Pallet su Traslatore DX

      U     "M168.1";
      UN    "M55.3";
      UN    "M55.4";
      U     DB98.DBX  193.1;
      U     "M171.2";
      UN    "M173.0";
      U     "M17.2";
      =     "M172.4";
NETWORK
TITLE =Com Aut Sbloccaggio Pallet su Traslatore DX

      U     "M168.1";
      U(    ;
      U     "M171.2";
      U     "M173.0";
      ON    "M171.2";
      O     "M55.3";
      O     "M55.4";
      )     ;
      U     "M17.1";
      =     "M172.5";
NETWORK
TITLE =Com Aut Discesa Allineatore traslatore zona di scarico Dx

      U     "M168.1";
      U     "EV611";
      U     "M57.5";
      =     "M177.0";
NETWORK
TITLE =Com Aut Salita Allineatore traslatore zona di scarico Dx

      U     "M168.1";
      U     "EV610";
      U     "M57.4";
      =     "M177.1";
NETWORK
TITLE =Com Aut Chiusura Allineatore traslatore zona di scarico Dx

      U     "M168.1";
      U     "EV115";
      U     "M140.5";
      U     "M140.6";
      UN    "M177.3";
      UN    "M177.4";
      U     "M57.7";
      =     "M177.2";
NETWORK
TITLE =Com Aut Apertura Allineatore traslatore zona di scarico Dx

      U     "M168.1";
      U(    ;
      U     "EV117";
      U     "M140.7";
      O     ;
      U     "M177.3";
      UN    "M172.6";
      )     ;
      U     "M140.5";
      UN    "M177.4";
      U     "M57.6";
      =     "M177.3";
NETWORK
TITLE =Aut Allineatore traslatore zona di scarico Dx ciclo eseguito

      U(    ;
      U     "M168.1";
      U     "M177.3";
      U     "M140.5";
      U     "M140.6";
      O     "M177.4";
      )     ;
      UN    "EV610";
      =     "M177.4";
NETWORK
TITLE =Com Aut Apertura Allineatore trasl. zona di scarico Dx Sicurezza
//Sicurezza Apertura allineatore dopo un nuovo avvio del ciclo nel caso
//l'operatore lo dimenticasse chiuso.
      U     "M168.1";
      U(    ;
      O     "M140.4";
      O     ;
      U     "M140.5";
      U     "M177.4";
      )     ;
      UN    "M140.6";
      =     "M177.5";
NETWORK
TITLE =Scarico Pallet DX Terminato (OK per Uscita Pallet Vuoto)

      U(    ;
      U     "M55.0";
      U     "M196.0";
      O     ;
      U     "M55.1";
      U     "M190.0";
      O     ;
      U     "M55.2";
      UN    DB98.DBX  193.0;
      U     "M184.0";
      O     ;
      U     "M55.2";
      U     DB98.DBX  193.0;
      U     "M190.0";
      )     ;
      U(    ;
      L     DB102.DBD   40;
      L     L#750000;
      <=D   ;
      )     ;
      FP    M    254.2;
      S     "M172.6";
      U     "M173.0";
      UN    "M171.2";
      R     "M172.6";
      NOP   0;
NETWORK
TITLE =Ciclo Traslatore DX Terminato

      U     "M172.6";
      UN    "M171.0";
      UN    "M171.3";
      U     "EV613";
      U(    ;
      O     "M171.1";
      ON    DB98.DBX  193.2;
      O     ;
      U(    ;
      UN    "M173.1";
      U     "EV646";
      O     "M58.7";
      )     ;
      UN    "M171.1";
      )     ;
      U     "M171.2";
      U     "EV603";
      U     "EV604";
      U     "EV611";
      S     "M173.0";
      U     "M171.3";
      U     "R24";
      R     "M173.0";
      NOP   0;
NETWORK
TITLE =Com Aut Salita Traslatore di Scarico SX

      U     "M168.1";
      UN    "M55.3";
      UN    "M55.4";
      U     DB98.DBX  193.2;
      U(    ;
      UN    "M175.0";
      U     "M171.0";
      UN    "M171.1";
      U(    ;
      O     "M171.2";
      O     ;
      UN    DB98.DBX  193.1;
      U     DB98.DBX  193.2;
      )     ;
      O     ;
      U     "M175.0";
      UN    "M171.0";
      U     "M171.1";
      U     "EV603";
      )     ;
      U     "M16.1";
      UN    "EV602";
      =     "M174.0";
NETWORK
TITLE =Com Aut Discesa Traslatore di Scarico SX

      U     "M168.1";
      U(    ;
      U     DB98.DBX  193.2;
      U(    ;
      UN    "M175.0";
      UN    "M171.0";
      U     "M171.1";
      U     "EV607";
      O     ;
      U     "M175.0";
      U     "M171.0";
      UN    "M171.1";
      )     ;
      O     "M55.3";
      O     "M55.4";
      )     ;
      U     "M16.2";
      =     "M174.1";
NETWORK
TITLE =Com Aut Start Avanti Catena Traslatore SX

      U     "M168.1";
      U     DB98.DBX  193.2;
      UN    "M55.3";
      UN    "M55.4";
      UN    "M175.0";
      UN    "M171.1";
      U     "EV600";
      U     "M19.6";
      =     "M174.2";
NETWORK
TITLE =Com Aut Start Indietro Catena Traslatore SX

      U     "M168.1";
      U     DB98.DBX  193.2;
      UN    "M55.3";
      UN    "M55.4";
      U     "M175.0";
      UN    "M171.0";
      U     "EV600";
      U     "M19.6";
      =     "M174.3";
NETWORK
TITLE =Com Aut Bloccaggio Pallet su Traslatore SX

      U     "M168.1";
      U     DB98.DBX  193.2;
      UN    "M55.3";
      UN    "M55.4";
      UN    "M175.0";
      U     "M171.1";
      U     "M17.0";
      =     "M174.4";
NETWORK
TITLE =Com Aut Sbloccaggio Pallet su Traslatore SX

      U     "M168.1";
      U(    ;
      U     "M175.0";
      U     "M171.1";
      ON    "M171.1";
      O     "M55.3";
      O     "M55.4";
      )     ;
      U     "M16.7";
      =     "M174.5";
NETWORK
TITLE =Com Aut Discesa Allineatore traslatore zona di scarico Sx

      U     "M168.1";
      U     "EV607";
      U     "M57.1";
      =     "M178.0";
NETWORK
TITLE =Com Aut Salita Allineatore traslatore zona di scarico Sx

      U     "M168.1";
      U     "EV606";
      U     "M57.0";
      =     "M178.1";
NETWORK
TITLE =Com Aut Chiusura Allineatore traslatore zona di scarico Sx

      U     "M168.1";
      U     "EV111";
      U     "M140.1";
      U     "M140.2";
      UN    "M178.3";
      UN    "M178.4";
      U     "M57.3";
      =     "M178.2";
NETWORK
TITLE =Com Aut Apertura Allineatore traslatore zona di scarico Sx

      U     "M168.1";
      U(    ;
      U     "EV113";
      U     "M140.3";
      O     ;
      U     "M178.3";
      UN    "M174.6";
      )     ;
      U     "M140.1";
      UN    "M178.4";
      U     "M57.2";
      =     "M178.3";
NETWORK
TITLE =Aut Allineatore traslatore zona di scarico Sx ciclo eseguito

      U(    ;
      U     "M168.1";
      U     "M178.3";
      U     "M140.1";
      U     "M140.2";
      O     "M178.4";
      )     ;
      UN    "EV606";
      =     "M178.4";
NETWORK
TITLE =Com Aut Apertura Allineatore trasl. zona di scarico Sx Sicurezza
//Sicurezza Apertura allineatore dopo un nuovo avvio del ciclo nel caso
//l'operatore lo dimenticasse chiuso.
      U     "M168.1";
      U(    ;
      O     "M140.0";
      O     ;
      U     "M140.1";
      U     "M178.4";
      )     ;
      UN    "M140.2";
      =     "M178.5";
NETWORK
TITLE =Scarico Pallet SX Terminato (OK per Uscita Pallet Vuoto)

      U(    ;
      U     "M55.0";
      U     "M236.0";
      O     ;
      U     "M55.1";
      U     "M230.0";
      O     ;
      U     "M55.2";
      UN    DB98.DBX  193.0;
      U     "M224.0";
      O     ;
      U     "M55.2";
      U     DB98.DBX  193.0;
      U     "M230.0";
      )     ;
      U(    ;
      L     DB102.DBD   40;
      L     L#750000;
      <=D   ;
      )     ;
      FP    M    254.3;
      S     "M174.6";
      U     "M175.0";
      UN    "M171.1";
      R     "M174.6";
      NOP   0;
NETWORK
TITLE =Ciclo Traslatore SX Terminato

      U     "M174.6";
      UN    "M171.0";
      U     "M171.1";
      UN    "M171.3";
      U     "EV613";
      U(    ;
      O     "M171.2";
      ON    DB98.DBX  193.1;
      O     ;
      U(    ;
      UN    "M173.1";
      U     "EV646";
      O     "M58.7";
      )     ;
      UN    "M171.2";
      )     ;
      U     "EV601";
      U     "EV604";
      U     "EV607";
      UN    "M173.0";
      S     "M175.0";
      U     "M171.3";
      U     "R24";
      R     "M175.0";
      NOP   0;
NETWORK
TITLE =Pallet Scaricato in Traslazione su Traslatore Finale

      U     "M168.1";
      U     "PX652";
      U     "R24";
      U(    ;
      O     "M173.0";
      O     "M175.0";
      )     ;
      S     "M175.1";
      U     "M171.3";
      U     "M168.1";
      UN    "PX652";
      U     "R24";
      R     "M175.1";
      NOP   0;
NETWORK
TITLE =Com Aut Salita Traslatore Finale

      U     "M168.1";
      U     "M171.3";
      UN    "M171.4";
      U     "M17.3";
      =     "M176.0";
NETWORK
TITLE =Com Aut Discesa Traslatore Finale

      U     "M168.1";
      UN    "M171.3";
      U     "M171.4";
      U     "M17.4";
      =     "M176.1";
NETWORK
TITLE =Com Aut Start Motore Catena Traslatore Finale

      U     "M168.1";
      U     "EV612";
      U     "M18.5";
      =     "M176.2";
END_FUNCTION

